Omron CX-Programmer project NuevoProyecto (CX-Programmer 9.51)

# PLC NuevoPLC1: CJ1M CPU12
I/O table (CPU CJ1M-CPU12): rack 0 slot 0 CJ1W-DRM21; rack 0 slot 1 CJ1W-ID211; rack 0 slot 2 CJ1W-ID211; rack 0 slot 3 CJ1W-ID211; rack 0 slot 4 CJ1W-OD212; rack 0 slot 5 CJ1W-OC211; rack 0 slot 6 CJ1W-OC211; rack 0 slot 7 CJ1W-ID211

## Global symbols (name address type ; comment)
Acceleracio _INVDRT401_WriteParameter
Acceleracio_SP D1200 UINT  ; Consigna d'acceleració
ActivarExpulsor 11.11 BOOL  ; 13Y1 Expulsor Activat
Alarma 60.00 BOOL  ; Alarma genèrica
Alarma00 61.00 BOOL  ; Protecció tèrmica equip rebobinador
Alarma01 61.01 BOOL  ; Protecció tèrmica equip arrosegament
Alarma02 61.02 BOOL  ; Protecció tèrmica equip carro
Alarma03 61.03 BOOL  ; Protecció tèrmica equip alineador
Alarma04 61.04 BOOL  ; Motor alineador no preparat
Alarma05 61.05 BOOL  ; Tèrmic extractor de retall
Alarma06 61.06 BOOL  ; Detectors de retall
Alarma07 61.07 BOOL  ; Alarma pressió aire
Alarma08 61.08 BOOL
Alarma09 61.09 BOOL
Alarma10 61.10 BOOL
Alarma11 61.11 BOOL
Alarma12 61.12 BOOL
Alarma13 61.13 BOOL
Alarma14 61.14 BOOL
Alarma15 61.15 BOOL
Alarma16 62.00 BOOL
Alarma17 62.01 BOOL
Alarma18 62.02 BOOL
Alarma19 62.03 BOOL
Alarma20 62.04 BOOL
Alarma21 62.05 BOOL
Alarma22 62.06 BOOL
Alarma23 62.07 BOOL
Alarma24 62.08 BOOL
Alarma25 62.09 BOOL
Alarma26 62.10 BOOL
Alarma27 62.11 BOOL
Alarma28 62.12 BOOL
Alarma29 62.13 BOOL
Alarma30 62.14 BOOL
Alarma31 62.15 BOOL
AlarmaActiva 60.02 BOOL  ; Alarma activa
AlarmaCritica 60.01 BOOL  ; Alarma critica, aturada inmediata de màquina
AlarmaCritica00 63.00 BOOL  ; Paro d'emergència activat
AlarmaCritica01 63.01 BOOL  ; Motor rebobinador no preparat
AlarmaCritica02 63.02 BOOL  ; Motor arrastre no preparat
AlarmaCritica03 63.03 BOOL  ; Motor carro no preparat
AlarmaCritica04 63.04 BOOL  ; Braç suport rebobinador fora de posició
AlarmaCritica05 63.05 BOOL  ; Porta desbobinador oberta
AlarmaCritica06 63.06 BOOL  ; Seguretat diametre màxim de bobina
AlarmaCritica07 63.07 BOOL  ; Seguretat pisor 1 endarrera
AlarmaCritica08 63.08 BOOL  ; Seguretat pisor 2 endarrera
AlarmaCritica09 63.09 BOOL
AlarmaCritica10 63.10 BOOL
AlarmaCritica11 63.11 BOOL
AlarmaCritica12 63.12 BOOL
AlarmaCritica13 63.13 BOOL
AlarmaCritica14 63.14 BOOL
AlarmaCritica15 63.15 BOOL
AlarmaCritica16 64.00 BOOL
AlarmaCritica17 64.01 BOOL
AlarmaCritica18 64.02 BOOL
AlarmaCritica19 64.03 BOOL
AlarmaCritica20 64.04 BOOL
AlarmaCritica21 64.05 BOOL
AlarmaCritica22 64.06 BOOL
AlarmaCritica23 64.07 BOOL
AlarmaCritica24 64.08 BOOL
AlarmaCritica25 64.09 BOOL
AlarmaCritica26 64.10 BOOL
AlarmaCritica27 64.11 BOOL
AlarmaCritica28 64.12 BOOL
AlarmaCritica29 64.13 BOOL
AlarmaCritica30 64.14 BOOL
AlarmaCritica31 64.15 BOOL
AlineadorReady 3340.05 BOOL  ; Equip Alineador ready
AnalogOutFreDesbo _INVDRT401_WriteParameter
ArrancExtractorRetall 12.02 BOOL  ; 17K2 Arranc extractor de retall
ArrosegamentReady 3320.05 BOOL  ; Equip Arrosegament ready
110.00 BOOL  ; Friccio eix 1 busy
110.01 BOOL  ; Senyal friccio eix 2 busy
111.00 BOOL  ; Off/On freno rebobinador
200.00 BOOL  ; AuxAccelBusy
200.01 BOOL  ; AuxDesaccelBusy
200.02 BOOL  ; Peticio actualitzacio acceleracio
200.03 BOOL  ; Actualitzacio acceleracio finalitzada
200.04 BOOL  ; Peticio actualitzacio desacceleracio
200.05 BOOL  ; Actualitzacio desacceleracio finalitzada
2960.08 BOOL  ; Entrada comptatge lector de marques
301.00 BOOL  ; Senyal consigna fre busy
301.01 BOOL  ; Senyal diametre desbo busy
302.00 BOOL  ; Auxiliar senyal desbobinador
304.00 BOOL  ; Aux Run Fw alineador manual
304.01 BOOL  ; Aux Run Rv alineador manual
3210.00 BOOL  ; Run Fw motor rebobinador
3210.01 BOOL  ; Run Rv motor rebobinador
3211 CHANNEL  ; Velocitat en Hz motor rebo
3221 CHANNEL  ; Referencia frequencia equip arrosegament en Hz
3231 CHANNEL  ; Referencia velocitat equip carro
3241 CHANNEL  ; Referencia velocitat alineador
3311.00 BOOL  ; Protecció termic RW
3321 CHANNEL  ; Feedback frequencia equip arrosegament
3360 CHANNEL  ; Diametre rebobinador
400.00 BOOL  ; Senyal Pressio pisor 1 busy
400.04 BOOL  ; Finalitzada actualitzacio de presio de pisor 1
400.05 BOOL  ; Peticio actualitzacio pressio pisor 1
400.06 BOOL  ; Finalitzacio actualitzacio pressio pisor 2
400.07 BOOL  ; Peticio actualitzacio pressio pisor 2
401 CHANNEL  ; Sequencia carro
402.00 BOOL  ; Reset encoder carro
402.01 BOOL  ; busy preset carro
403.02 BOOL  ; Auxiliar carro fw
403.03 BOOL  ; Auxiliar carro Rv
403.04 BOOL  ; AuxMotorCarro
403.05 BOOL  ; AuxMotorBrasos
403.06 BOOL  ; Retard Conexio Contactor
403.07 BOOL  ; Tope carro darrera
410 CHANNEL  ; Sequencia pujar/baixar braços
410.00 BOOL  ; Pujar motor braços suport
410.01 BOOL  ; Baixar motor braços suport eixos
420.00 BOOL  ; Generar preset de posició encoder
500.00 BOOL  ; Mode alineador
500.01 BOOL  ; AuxAlineadorFw
500.02 BOOL  ; AuxAlineadorRv
500.03 BOOL  ; Actualitzacio guany P alineador feta
500.04 BOOL  ; Flanc inici alineador mode automàtic
500.05 BOOL  ; Ok inici run alineador mode automàtic
500.06 BOOL  ; Ctrl mode velocitat alineador
501.02 BOOL  ; Peticio actualitzacio guany P alineador
51 CHANNEL  ; Estat Màquina
52.03 BOOL  ; Màquina en moviment
52.04 BOOL  ; Condicions braços suport Ok
54.00 BOOL  ; Senyal inici paro per metres
54.01 BOOL  ; Paro per diametre desbobinador
54.02 BOOL  ; Senyal paro automatic per diametre desbo
54.03 BOOL  ; ParoPerDiametreDesbo
54.04 BOOL  ; DiametreReboSuperat
54.15 BOOL  ; Senyal paro automàtic comptadors
600.01 BOOL  ; Aux pinces carro rebo menys
D10000 CHANNEL  ; ç
D1100 CHANNEL  ; Fricció eix 1
D1101 CHANNEL  ; Fricció eix 2
D1112 CHANNEL  ; Decreixent tiro rebobinador
D1113 CHANNEL  ; Ample bobina rebo 1
D1114 CHANNEL  ; Pressio friccio rebo 1
D1122 CHANNEL  ; Decreixent tieo rebo 2
D1123 CHANNEL  ; Ample bobina rebo 2
D1130 CHANNEL  ; Offset corba parell eix friccio
D1131 CHANNEL  ; Sortida pressio mínima
D1205 CHANNEL  ; Selecció actual desacceleració
D1400 CHANNEL  ; Pressio pisor eix 1
D1401 CHANNEL  ; Auxiliar presió pisor 1
D1402 CHANNEL  ; Posició pisor eix 1
D1403 CHANNEL  ; Posició pisor eix 2
D1405 CHANNEL  ; Error posició pisor 1
D1410 CHANNEL  ; Pressio pisor 2
D1412 CHANNEL  ; Posicio pisor rebo 2
D1415 CHANNEL  ; Error posicio pisor 2
D1420 CHANNEL  ; Tope carro endarrera
D1490 CHANNEL  ; Tope carro enrera
D1500 CHANNEL  ; Tensió capçar alineador
D1501 CHANNEL  ; ErrorAlineador
D1502 CHANNEL  ; Velocitat maxima alineador Fw
D1503 CHANNEL  ; Velocitat alineador maxima Rv
D1505 CHANNEL  ; Velocitat inici alineador
D1510 CHANNEL  ; Guany P alineador
D1520 CHANNEL  ; Aux Guany P alineador
D1601 CHANNEL  ; Velocitat minima deteccio retall
D1602 CHANNEL  ; Mode avis/paro detectors retall
D216 CHANNEL  ; MetresParoDesbo
H100.00 BOOL  ; Forçar pisor arrosegament
H110.00 BOOL  ; Sentit bobinat
H120.00 BOOL  ; Sentit Alineador
H150.00 BOOL  ; OffOnDetectorRetall1
H150.01 BOOL  ; OffOnDetectorRetall2
H54.00 BOOL  ; Off/On paro per metres
H54.01 BOOL  ; Off/On paro per diametre rebo
H54.02 BOOL  ; Off/On paro per diametre desbobinador
T0051 BOOL  ; Retard apagar ventiladors motors
T0052 BOOL  ; Temps avis alarma
T0053 BOOL  ; Tim avis acustic nou avis
T0054 BOOL  ; Tim avis pistons pneumatics braços
T0100 BOOL  ; Tim presostat aire
T0300 BOOL  ; Retard obertura desbo
T0301 BOOL  ; Retard a la desconexió de la central hidraulica
T0302 BOOL  ; Retard a la desconexió del pisto posició vertical handling
T0303 BOOL  ; Retard a la desconexió del pisto carrega bobines handling
T0400 BOOL  ; Temporitzador retard a la conexió dels contactors de selecció de motor
T0500 BOOL  ; Retard a la conexió del Run alineador respecte el PID
AuxAcceleracio_SP D1201 UINT  ; Auxiliar consigna acceleració
AuxCalcul0 W0 CHANNEL  ; Auxiliar Calcul
AuxCalcul1 W1 CHANNEL  ; Auxiliar Calcul
AuxCalcul2 W2 CHANNEL  ; Auxiliar Calcul
AuxCalcul3 W3 CHANNEL  ; Auxiliar Calcul
AuxCalcul4 W4 CHANNEL  ; Auxiliar Calcul
AuxCalcul5 W5 CHANNEL  ; Auxiliar Calcul
AuxCalcul6 W6 CHANNEL  ; Auxiliar Calcul
AuxDCalcul0 W10 DINT
AuxDCalcul1 W12 DINT
AuxDesacceleracio_SP D1203 UINT  ; Auxiliar consigna desacceleracio
AuxDiametreDresbo_PV D1301 INT  ; Diametre actual desbobinador format %
AuxHusilloDreta 300.00 BOOL  ; Maniobra obrir tencar i desfasar desbo EASY
AuxHusilloEsquerra 300.01 BOOL  ; Maniobra obrir tencar i desfasar desbo EASY
Aux_Paro_Handling 700.00 BOOL  ; Auxiliar Paro Handling
Avis00 81.00 BOOL  ; Pinces carro activades
Avis01 81.01 BOOL  ; Equip rebobinador no preparat
Avis02 81.02 BOOL  ; Equip arrosegament no preparat
Avis03 81.03 BOOL  ; Equip carro no preparat
Avis04 81.04 BOOL  ; Equip alineador no preparat
Avis05 81.05 BOOL  ; Cierres rebobinador posats en intentar moure braços
Avis06 81.06 BOOL  ; Cierres rebobinador trets en intentar donar marxa
Avis07 81.07 BOOL  ; Desbobinador fora de posicio al intentar donar marxa a maquina
Avis08 81.08 BOOL  ; Braços de suport rebobinador fora de posicio
Avis09 81.09 BOOL  ; Pisor arrosegament no baixat en el moment de marxa
Avis10 81.10 BOOL  ; Detectors retall
Avis11 81.11 BOOL  ; Proteccio ganivetas circulars oberta
Avis12 81.12 BOOL  ; Porta seguretat desbobinador oberta
Avis13 81.13 BOOL  ; Expulsors bobines a carrega
Avis14 81.14 BOOL  ; Emegencia Handling
AvisosActius 80.00 BOOL  ; Avisos actius
BI_Centrat 1.12 BOOL  ; 54BI4 Detector posició central alineador desbo EASY
BI_PosicioBraçHoritzontal 3.08 BOOL  ; 22BI1 Detector Handling Posicio Horitzontal
BI_PosicioBraçVertical 3.09 BOOL  ; 22BI2 Detector Handling Posicio Vertical
BI_PosicioPerxaCarrega 3.10 BOOL  ; 22BI3 Detector Handling Posicio Carrega
BI_PosicioPerxaDesrarrega 3.11 BOOL  ; 22BI4 Detector Handling Posicio Descarrega
BI_SeguretatBraçosAmun 2.08 BOOL  ; 14BI3 Posicio braços suport amunt
BI_SeguretatHusillo 1.14 BOOL  ; 54BI6 Detector desbo EASY seguretat husillo
BI_TopeCostatCilindre 1.15 BOOL  ; 54BI7 Detector tope costat cilindre desbo EASY
BI_TopeCostatHusillo 1.10 BOOL  ; 54BI2 Detector desbo EASY tope costat husillo
BI_TopeDesfasaeDreta 1.13 BOOL  ; 54BI5 Detector tope desfasar dreta desbobinador EASY
BI_TopeDesfasarEsquerra 1.11 BOOL  ; 54BI3 Detector desbo EASY tope desfasar esquerra
BaixarDesbobinador 12.07 BOOL  ; 58Y2 Baixar desbobinador
BarresAntiestatica 11.10 BOOL  ; 16K1 Barres antiestàtiques
BarresAntiestatica_Muntat H0.06 BOOL  ; Barres antiestàtiques muntades a màquina
BraçHandlingHoritzontal 12.10 BOOL  ; 62Y2 Braç Handling Posicio Hotirzontal
BraçHandlingVertical 12.09 BOOL  ; 62Y1 Braç Handling Posicio Vertical
CarroManualFw 401.01 BOOL  ; Moviment carro endevant manual
CarroManualRv 401.03 BOOL  ; Moviment carro endarrera manual
CarroManualStopFw 401.02 BOOL  ; Para moviment endevant carro en manual
CarroManualStopRv 401.00 BOOL  ; Para moviment endarrera carro en manual
CarroReady 3330.05 BOOL  ; Equip Carro ready
CentralHidraulica 12.05 BOOL  ; 57K1 Central hidràulica
Claxon 10.09 BOOL  ; Claxon
CntMetresParcial D202 INT  ; Registre comptatge metres
CntMetresTotal D206 DINT  ; Totalitzador metres
CntPulsosParcial D200 INT  ; Comptador de metres actual
CntPulsosTotal D204 DINT  ; Comptador pulsos lleva totals
ComptaMetres 0.14 BOOL  ; 24BI1 Inductiu lleva comptamentres
ComptadorMarques D220 DINT  ; Lectura comptador de marques
CondicionsMarxaOK 52.00 BOOL  ; Condicions per a l'inici de la marxa de màquina
CtrlFreArrosegament 100.01 BOOL  ; Off/On Fre arrosegament
CtrlPisorArrosegament 100.00 BOOL  ; Off/On pisor arrosegament
CtrlVelocitatSeguretat D106 INT  ; Velocitat de seguretat de control
DB_CapsalAlineador _INVDRT201_ReadParameter
DB_DiametreDesbo Escalat
DB_DiametreDesbo_PV _INVDRT201_ReadParameter
DB_ErrorAlineador Escalat
DB_ErrorPosicioPisor1 Escalat
DB_ErrorPosicioPisor2 Escalat
DB_Fre Escalat
DB_VelocitatActual Escalat
DB_VelocitatLineaHz Escalat
DemHidraHandling 700.02 BOOL  ; Demanda central hidraulica handlind
Desacceleracio _INVDRT401_WriteParameter
Desacceleracio_SP D1202 UINT  ; Consigna desacceleracio
DesactivarExpulsor 11.12 BOOL  ; 13Y2 Desactivar Expulsor
DetectorRetall1 2.11 BOOL  ; 17BF1 Detector extractor de retall 1
DetectorRetall2 2.12 BOOL  ; 17BF2 Detector extractor de retall 2
DetectorsRetall_Muntat H0.03 BOOL  ; Detectors extractor de retall muntats a la màquina
DiametreDesbo_PV D1302 INT  ; Diametre desbobinador en mm
DiametreMaximDesbo D1304 INT  ; Diametre màxim desbobinador en mm
DiametreMaximRebo D1105 INT  ; Diametre màxim rebobinador
DiametreMinimDesbo D1305 INT  ; Diametre core desbobinador
DiametreMinimRebo D1104 INT  ; Diametre mínim de rebobinador
DiametreStopDesbo D212 INT  ; Diametre paro automàtic desbobinador
DiametreStopRebo D213 INT  ; Diametre paro automatic rebobinador
DistanciaMarques D222 DINT  ; Distancia entre marques en mm
EmergenciaHandling 3.12 BOOL  ; Handling en estat d'emergencia
Emergència 0.00 BOOL  ; Relé de seguretat
EnclavamentPortaDesbo 10.11 BOOL  ; 16K1 Enclavament seguretat porta desbobinador
EquipsReady 52.02 BOOL  ; Equips ready
Escaner_Seguretat 3.13 BOOL  ; Escaner Seguretat
Estat 50 WORD  ; Bits d'estat de màquina
EstatDetectorsRetall 151.00 BOOL  ; Detectors retall Ok
EstatMaquinaParadaOk 52.01 BOOL  ; Condicions de màquina aturada
Estat_Alarma 50.01 BOOL  ; Màquina en estat d'alarma
Estat_Enfilat 50.06 BOOL  ; Màquina amb marxa d'enfilat
Estat_Marxa 50.04 BOOL  ; Màquina en producció
Estat_Paro 50.05 BOOL  ; Màquina en procés de paro convencional
Estat_Preparacio 50.03 BOOL  ; Maquina en estat de preparació
Estat_Stop 50.02 BOOL  ; Màquina aturada sense alarmes
Estat_emergència 50.00 BOOL  ; Màquina en estat de paro d'emergència
ExpulsorFora 3.02 BOOL  ; 13B1 Reed Expulsor Fora
ExpulsorHome 3.03 BOOL  ; 13B2 Reed Expulsor Home
Expulsors_Muntats H0.10 BOOL  ; Expulsors instal.lats a màquina
ExtractorRetall 12.01 BOOL  ; 17K1 Extractor retall
ExtractorRetall_Muntat H0.01 BOOL  ; Extractor de retall muntat a la màquina
FlagVelocitatSeguretat 52.05 BOOL  ; Senyal màquina en velocitat de seguretat
ForçarExtractorRetall H101.00 BOOL  ; Forçar extractor de retall
Fre Escalat
FreArrosegament 11.05 BOOL  ; 33Y2 Fre arrosegament
FreRebobinador 11.00 BOOL  ; 14Y1 Fre rebobinador
FriccioEix1 FriccioEix1
FriccioRebo1 FriccioEix2
FriccioRebo2 FriccioEix2
Friccio_1_Prova _INVDRT401_WriteParameter
FriccióEix1 _INVDRT401_WriteParameter
FriccióEix2 _INVDRT401_WriteParameter
GruixMaterial D211 INT  ; Espesor
GuanyOutPID_Alineador _INVDRT401_WriteParameter
Handling_Muntat H0.09 BOOL  ; Hanfling instal.lat a màquina
LaserMandrins 11.09 BOOL  ; 15K1 Laser posicionador mandrins
LaserMandrins_Muntat H0.04 BOOL  ; Laser posicionat mandrins muntats a la màquina
LectorMarques H0.08 BOOL  ; Lector de marques muntat
ManAutHandling 700.01 BOOL  ; Handling en manual automàtic
Metres2Marques D228 INT  ; Conversió el preset de marques a metres
MetresAproximacio D210 INT  ; Metres aproximació
MetresMarques D224 INT  ; Conversió de marques a mm
MetresParoAutomatic D208 INT  ; Metres de bobina per paro automatic
ModeAcceleracio 53.00 BOOL  ; Mode Acceleracio auto/man
ModeVelocitat 53.01 BOOL  ; Velocitat On=Ràpida Off=Lenta
MotorBraçosSuport 12.04 BOOL  ; 24K2 Contactor selecció motor braços suport
MotorCarro 12.03 BOOL  ; 24K1 Contactor selecció motor carro
ObrirDesboEASY 11.08 BOOL  ; 54Y2 Obrir desbobinador EASY
OffOnBarresAntiestàtiques H110.01 BOOL  ; Off/On barres antiestàtiques
OffOnDesbo 300.02 BOOL  ; Biestable Off/On desbobinador
OffOnExtractorRetall 150.00 BOOL  ; Off/On extractor de retall
OffOnLaserMandrins 150.01 BOOL  ; Off/On Laser posicionat mandrins
OffOnMarques H54.03 BOOL  ; Off/On paro per marques
OffOnPID_Alineador _INVDRT401_WriteParameter
OffsetEscalatDiametreDesbo D1303 INT  ; Offset escalat diametre desbo
OffsetFre D1313 INT  ; Offset sortida fre
OnOffTanquesBraços 11.13 BOOL  ; 14K2 Obrir/tancar pistons pneumatics braços
OscilacioGanivetas 12.08 BOOL  ; 18K1 Contactor motor oscil.lacio ganivetas
OscilacioGanivetas_Muntat H0.02 BOOL  ; Oscilacio Ganivetas muntat a la màquina
PID_Alineador 3240.05 BOOL  ; Off/On PID Alineador
ParellFre_SP D1311 INT  ; Consigna fre a aplicar en %
ParellMaxFre D1312 INT  ; Parell màxim que pot exercir el fre en kg*m
ParoAutomatic 70.00 BOOL  ; Paro automatic de màquina
ParoDetRetall 151.01 BOOL  ; Paro per detectors retall
ParoMarques 54.05 BOOL  ; Paro per marques
ParoRapid D1204 INT  ; Temps desacceleració per paro ràpid
ParoRapidDetRetall 151.02 BOOL  ; Paro rapid per detectors retall
PerimetreArrosegament D201 INT  ; Perimetre rodillo arrosegament
PerxaCarrega 12.12 BOOL  ; 62Y4 Perxa Posicio Carrega
PerxaDescarrega 12.11 BOOL  ; 62Y3 Perxa Posicio Descarrega
PickUp_Muntat H0.00 BOOL  ; PickUp instal.lat a la màquina
PilotAlineador 10.07 BOOL  ; 44SH1 Pilot pulsador alineador
PilotContadorMarques 10.12 BOOL  ; 35SH1 Pilot pulsador contador marques
PilotDesbobinador 10.08 BOOL  ; 53SH1 Pilot pulsador desbobinador
PilotExtractor 10.04 BOOL  ; 17SH1 Pilot pulsador extractor de retall
PilotFreArrosegament 10.06 BOOL  ; 33SH2 Pilot pulsador fre arrosegament
PilotMarxa 10.02 BOOL  ; 08SH3 Pilot pulsador de marxa
PilotModeAcceleracio 10.03 BOOL  ; 08SH7 Pilot pulsador mode acceleració
PilotParo 10.01 BOOL  ; 08SH1 Pilot pulsador de paro
PilotPisorArrosegament 10.05 BOOL  ; 33SH1 Pilot pulsador pisor arrosegament
PilotReset 10.00 BOOL  ; 06SH1 Pilot pulsador de reset
PilotSelectorPorta 10.10 BOOL  ; 08SH15 Pilot selector obrir porta seguretat desbo
PincesCarroMenys 11.02 BOOL  ; 23Y1 Pinces carro a menys
PincesCarroMes 11.03 BOOL  ; 23Y2 Pinces carro a més
PisorArrosegament 11.04 BOOL  ; 33Y1 Pisor arrosegament
PisorRetenidor 11.06 BOOL  ; 34Y1 Pisor retenidor
PosicioPisor1 _INVDRT201_ReadParameter
PosicioPisor2 _INVDRT201_ReadParameter
PresetEncoderCarro _INVDRT401_WriteParameter
PresioMaximaFriccio D1107 INT  ; Pressió màxima
PresorRebobinador 11.01 BOOL  ; 14Y2 Presor rebobinador
PresostatGeneral 0.15 BOOL  ; 34B1 Presostat linea general
PressioPisor1 _INVDRT401_WriteParameter
PressioPisor2 _INVDRT401_WriteParameter
ProteccioTermicaAlineador 3344.00 BOOL  ; Protecció tèrmica Alineador entrada S1
ProteccioTermicaArrosegament 3324.00 BOOL  ; Protecció tèrmica Arrosegament entrada S1
ProteccioTermicaCarro 3334.00 BOOL  ; Protecció tèrmica Carro entrada S1
ProteccioTermicaRebo 3314.00 BOOL  ; Protecció tèrmica Rebo entrada S1
PujarDesbobinador 12.06 BOOL  ; Pujar Desbobinador
RebobinadorReady 3310.05 BOOL  ; Equip Rebobinador ready
RegistreAlarma 60 DWORD  ; Registre alarmes
RegistreAlarmaCritica 63 DWORD  ; Registre alarma crítica
RegistreAvisos 81 CHANNEL  ; Registre avisos
ResetAlineador 3240.09 BOOL  ; Reset equip alineador
ResetCarro 3230.09 BOOL  ; Reset equip carro
ResetMarques 55.00 BOOL  ; Reset comptador de marques
RunFwAlineador 3240.00 BOOL  ; Run Fw motor alineador
RunFwArrosegament 3220.00 BOOL  ; Senyal Run forward equip arrosegament
RunFwCarro 3230.00 BOOL  ; Run Carro Fw
RunRvAlineador 3240.01 BOOL  ; Run Rv motor alineador
RunRvArrosegament 3220.01 BOOL  ; Senyal Run reverse equip arrosegament
RunRvCarro 3230.01 BOOL  ; Run Carro Rv
SF_PortaSeguretatDesbo 2.14 BOOL  ; 08SF1 Detector porta seguretat On=Porta tencada Off=Porta oberta
SL_Ajustos 3.14 BOOL  ; 07SL2 Selector Ajustos
SL_BraçAbaix 0.11 BOOL  ; Selector braços suport eixos rebobinador abaix
SL_BraçAmun 0.10 BOOL  ; Selector braços suport eixos rebobinador amunt
SL_OscilacioGanivetas 2.10 BOOL  ; 18SL1 Selector oscil.lacio ganivetas
SL_PortaSeguretat 2.13 BOOL  ; 08SL15 Selector obrir porta seguretat
SP_ActivarExpulsor 3.00 BOOL  ; 13S1Pulsador Activar Expulsor
SP_Alineador 1.00 BOOL  ; 44SH1 Pulsador mode alineador
SP_Augmentar 0.07 BOOL  ; 08SP11 Pulsador augmentar velocitat
SP_BaixarDesbo 2.03 BOOL  ; 57SP1 Pulsador baixar desbobinador
SP_Carro 0.09 BOOL  ; 23SP1 Pulsador carro
SP_DesactivarExpulsor 3.01 BOOL  ; 13S1Pulsador Desactivar Expulsor
SP_Desbobinador 1.03 BOOL  ; SP Pulsador Off/On desbobinador
SP_DesfasarDreta 1.02 BOOL  ; 44SP5 Pulsador desfasar dreta
SP_DesfasarEsquerra 1.01 BOOL  ; 44SP3 Pulsador desfasar esquerra
SP_Disminuir 0.06 BOOL  ; 08SP9 Pulsador disminuir velocitat
SP_Enfilat 0.08 BOOL  ; 08SP13 Pulsador enfilat
SP_ExtractorRetall 2.00 BOOL  ; 17SH1 Pulsador Off/On extractor de retall
SP_FreArrosegament 0.13 BOOL  ; 33SH2 Pulsador Off/On fre arrosegament
SP_HandlingStop 3.07 BOOL  ; 61SP2 Pulsador Handling Stop
SP_Marxa 0.03 BOOL  ; 08SH3 Pulsador de marxa
SP_ModeAccel 0.05 BOOL  ; 08SH7 Pulsador mode acceleracio Manual/Automatica
SP_MovimentHandling 3.04 BOOL  ; 61SP1 Pulsador Moviment Handling
SP_ObrirDesbo 2.06 BOOL  ; 55SP1 Pulsador obrir desbobinador
SP_Paro 0.02 BOOL  ; 08SH1 Pulsador paro
SP_ParoRapid 0.04 BOOL  ; 08SP5 Pulsador paro ràpid
SP_PisorArrosegament 0.12 BOOL  ; 33SH1 Pulsador Off/On pisor arrosegament
SP_PujarDesbo 2.04 BOOL  ; 57SP2 Pulsador pujar desbobinador
SP_Reset 0.01 BOOL  ; 06SH1 Pulsador reset
SP_RotacioHandlingHoritzontal 3.05 BOOL  ; 61S1 Pulsador Rotacio Horitzontal Handling
SP_RotacioHandlingVertical 3.06 BOOL  ; 61S1Pulsador Rotacio Vertical Handling
SP_SeguretatDesbo 2.09 BOOL  ; 57SP3 Pulsador seguretat maniobra hidràulica
SP_TencarDesbo 2.07 BOOL  ; 55SP2 Pulsador tencar desbobinador
SafetyPLC H0.12 BOOL  ; Safety PLC installed
SclDiaDesboMax D2002 INT  ; Valor màxim entrada analogica diametre desbo escalat
SclDiaMaxDesbo D2001 INT  ; Diametre màxim desbo escalat
SclOffsetDiaDesbo D2000 INT  ; Offset escalat diametre desbo
SeguretatBraçAbaix 1.07 BOOL  ; 14SF2 Final de cursa seguretat posició braços suport rebobinador abaix
SeguretatBraçAmun 1.06 BOOL  ; 14SF1 Final de cursa seguretat posició braços suport rebobinador amun
SeguretatCirculars 2.15 BOOL  ; 08BI1 Detector seguretat protecció ganivetas circulars
SeguretatPincesCarro 1.08 BOOL  ; 23BI1 Reed seguretat pinces carro pisor a menys
SeguretatPisorOff 700.03 BOOL  ; Seguretat pisor totalment endavant
SeguretatPosicioDesbo 2.05 BOOL  ; 58SF1 Final de cursa seguretat posició Desbobinador
SeguretatTancamentRebo1 1.04 BOOL  ; 14BI1 Inductiu seguretat tancament rebobinador 1
SeguretatTancamentRebo2 1.05 BOOL  ; 14BI2 Inductiu seguretat tancament eix rebobinador 2
SeguretatTencarDesbo 1.09 BOOL  ; 54BI1 Reed seguretat cilindre tancament desbobinador
SobrevelocitatRebo D1103 INT  ; Sobrevelocitat rebobinador en m/min
SortidaFre D1314 WORD
TallCirculars_Muntat H0.07 BOOL  ; Tall de ganivetas circulars muntat
Tanques_Rebo_Muntats H0.11 BOOL  ; Tanques pneumatiques a màquina
TaperRebo1 D1111 INT  ; Taper tir rebobinador 1
TaperRebo2 D1121 INT  ; Taper tir rebobinador 2
TempsLaserMandrinsOn D1600 CHANNEL  ; Temps On Laser posicionat mandrins
TencarDesboEASY 11.07 BOOL  ; 54Y1 Tencar desbobinador EASY
TencatDesbo_Muntat H0.05 BOOL  ; Tencat desbobinador de seguretat muntat a màquina
TensioDesbo_SP D1310 INT  ; Consigna de fre al desbobinador
TimArrancExtractorRetall T0150 BOOL  ; Temporització per a l'arranc del extractor de retall
TimLaserMandrins T0151 BOOL  ; Temporització On laser mandrins
TimPisor1 T0101 BOOL  ; Temporització seguretat pisor1
TimPisor2 T0102 BOOL  ; Temporització seguretat pisor2
TimPreparacio T0050 BOOL  ; Temporització del estat de preparacio de marxa
TirMaximRebo D1106 INT  ; Tir màxim rebobinador
TirRebo1_SP D1110 INT  ; Consigna de tir rebobinador 1
TirRebo2_SP D1120 INT  ; Consigna de tir rebobinador 2
TiroDesboMax D1315 INT  ; Tiro màxim aplicable al desbo
TiroRebo1 Escalat
TiroRebo2 Escalat
TèrmicCentralHidràulica 2.02 BOOL  ; 57F1 Tèrmic central hidràulica
TèrmicExtractorRetall 2.01 BOOL  ; 17F1 Tèrmic extractor de retall
Velocitat0Arrosegament 3320.01 BOOL  ; Velocitat 0 equip arrosegament
Velocitat0Carro 3330.01 BOOL  ; Velocitat 0 equip carro
Velocitat0Rebo 3310.01 BOOL  ; Velocitat 0 equip rebo
VelocitatActual D110 INT  ; Velocitat actual de màquina m/min
VelocitatAuto D101 INT  ; Velocitat automàtica
VelocitatEnfilat D104 INT  ; Velocitat enfilat
VelocitatExpulsioBobines D107 INT  ; Velocitat del Rebobinador al expulsar bobina
VelocitatLenta D102 INT  ; Velocitat lenta
VelocitatLineaRebo D1102 CHANNEL  ; Velocitat en Hz de motor rebo
VelocitatMaxima D103 INT  ; Velocitat màxima
VelocitatSeguretat D105 INT  ; Velocitat de seguretat
VelocitatSeguretatPLC 10.13 BOOL  ; Velocitat seguretat PLC
Velocitat_SP D100 INT  ; Consigna velocitat
Velocitat_braços D112 INT  ; Velocitat braços
Velocitat_carro D1406 INT  ; Velocitat del carro
VentiladorsMotors 12.00 BOOL  ; 08K1 Contactor ventilació motors

## Program Màquina (cyclic task 0)
Local symbols
Aux_Paro_handling BOOL
Aux_StopHandling BOOL
BI_TopeDesfasarDreta BOOL
Estat_Emerencia BOOL
Estat_Emergencia BOOL
Estat_Emergència BOOL
Estat_emergencia BOOL
IR CHANNEL
P_G BOOL
P_GR BOOL
P_Ge BOOL
P_ON BOOL
P_on BOOL
S UINT
SP_Stop BOOL
sp_reset BOOL

### Section EstatMàquina

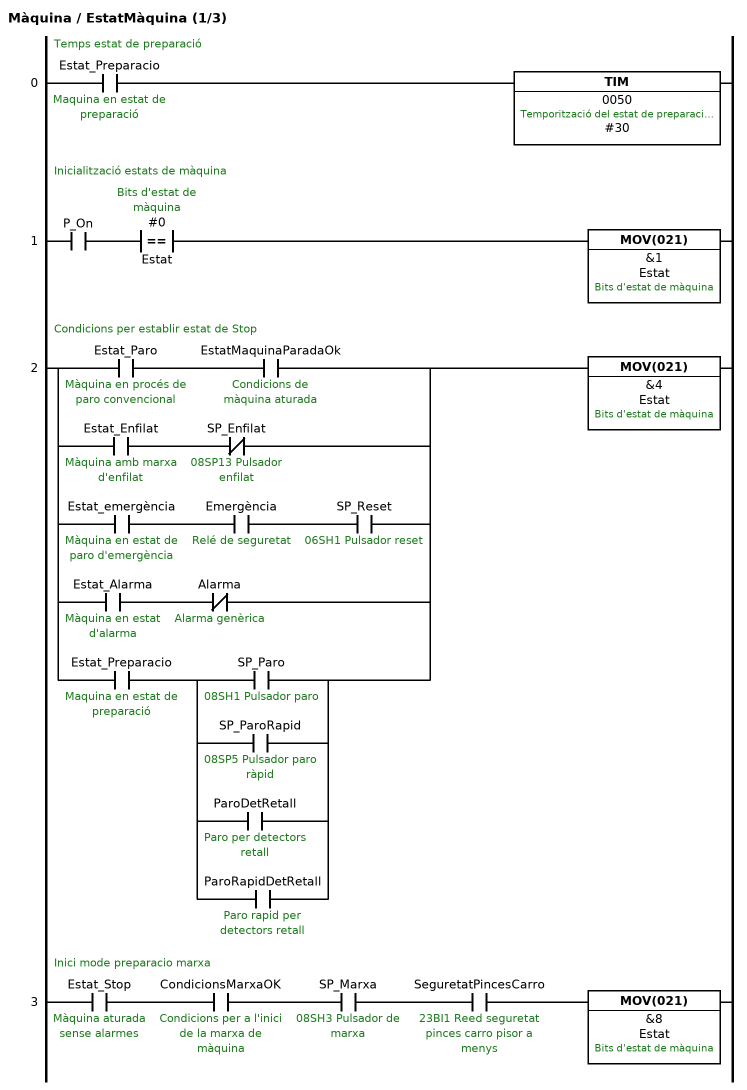
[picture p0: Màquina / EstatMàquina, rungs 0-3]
; rung 0: Temps estat de preparació
LD Estat_Preparacio  ; Maquina en estat de preparació
TIM 0050 #30  ; Temporització del estat de preparacio de marxa
; rung 1: Inicialització estats de màquina
LD P_On
AND=(300) #0 Estat  ; Bits d'estat de màquina
MOV(021) &1 Estat  ; Bits d'estat de màquina
; rung 2: Condicions per establir estat de Stop
LD Estat_Paro  ; Màquina en procés de paro convencional
AND EstatMaquinaParadaOk  ; Condicions de màquina aturada
LD Estat_Enfilat  ; Màquina amb marxa d'enfilat
ANDNOT SP_Enfilat  ; 08SP13 Pulsador enfilat
ORLD
LD Estat_emergència  ; Màquina en estat de paro d'emergència
AND Emergència  ; Relé de seguretat
AND SP_Reset  ; 06SH1 Pulsador reset
ORLD
LD Estat_Alarma  ; Màquina en estat d'alarma
ANDNOT Alarma  ; Alarma genèrica
ORLD
LD Estat_Preparacio  ; Maquina en estat de preparació
LD SP_Paro  ; 08SH1 Pulsador paro
OR SP_ParoRapid  ; 08SP5 Pulsador paro ràpid
OR ParoDetRetall  ; Paro per detectors retall
OR ParoRapidDetRetall  ; Paro rapid per detectors retall
ANDLD
ORLD
MOV(021) &4 Estat  ; Bits d'estat de màquina
; rung 3: Inici mode preparacio marxa
LD Estat_Stop  ; Màquina aturada sense alarmes
AND CondicionsMarxaOK  ; Condicions per a l'inici de la marxa de màquina
AND SP_Marxa  ; 08SH3 Pulsador de marxa
AND SeguretatPincesCarro  ; 23BI1 Reed seguretat pinces carro pisor a menys
MOV(021) &8 Estat  ; Bits d'estat de màquina

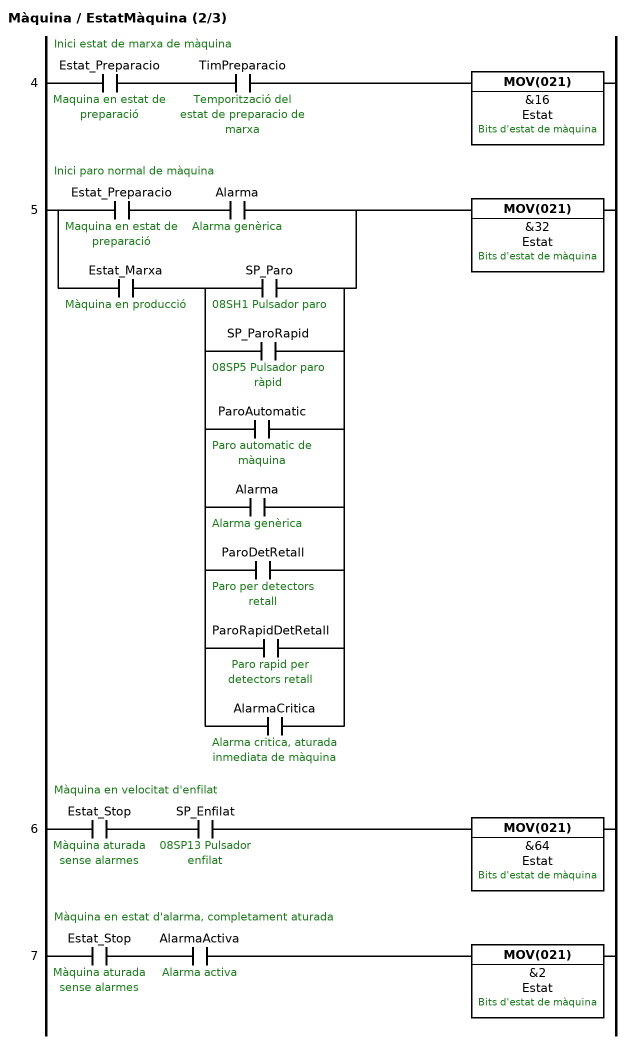
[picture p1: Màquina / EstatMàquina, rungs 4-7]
; rung 4: Inici estat de marxa de màquina
LD Estat_Preparacio  ; Maquina en estat de preparació
AND TimPreparacio  ; Temporització del estat de preparacio de marxa
MOV(021) &16 Estat  ; Bits d'estat de màquina
; rung 5: Inici paro normal de màquina
LD Estat_Preparacio  ; Maquina en estat de preparació
AND Alarma  ; Alarma genèrica
LD Estat_Marxa  ; Màquina en producció
LD SP_Paro  ; 08SH1 Pulsador paro
OR SP_ParoRapid  ; 08SP5 Pulsador paro ràpid
OR ParoAutomatic  ; Paro automatic de màquina
OR Alarma  ; Alarma genèrica
OR ParoDetRetall  ; Paro per detectors retall
OR ParoRapidDetRetall  ; Paro rapid per detectors retall
OR AlarmaCritica  ; Alarma critica, aturada inmediata de màquina
ANDLD
ORLD
MOV(021) &32 Estat  ; Bits d'estat de màquina
; rung 6: Màquina en velocitat d'enfilat
LD Estat_Stop  ; Màquina aturada sense alarmes
AND SP_Enfilat  ; 08SP13 Pulsador enfilat
MOV(021) &64 Estat  ; Bits d'estat de màquina
; rung 7: Màquina en estat d'alarma, completament aturada
LD Estat_Stop  ; Màquina aturada sense alarmes
AND AlarmaActiva  ; Alarma activa
MOV(021) &2 Estat  ; Bits d'estat de màquina

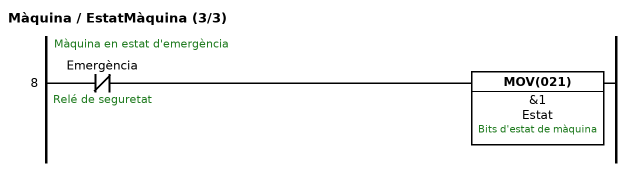
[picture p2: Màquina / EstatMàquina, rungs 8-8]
; rung 8: Màquina en estat d'emergència
LDNOT Emergència  ; Relé de seguretat
MOV(021) &1 Estat  ; Bits d'estat de màquina

### Section Principal

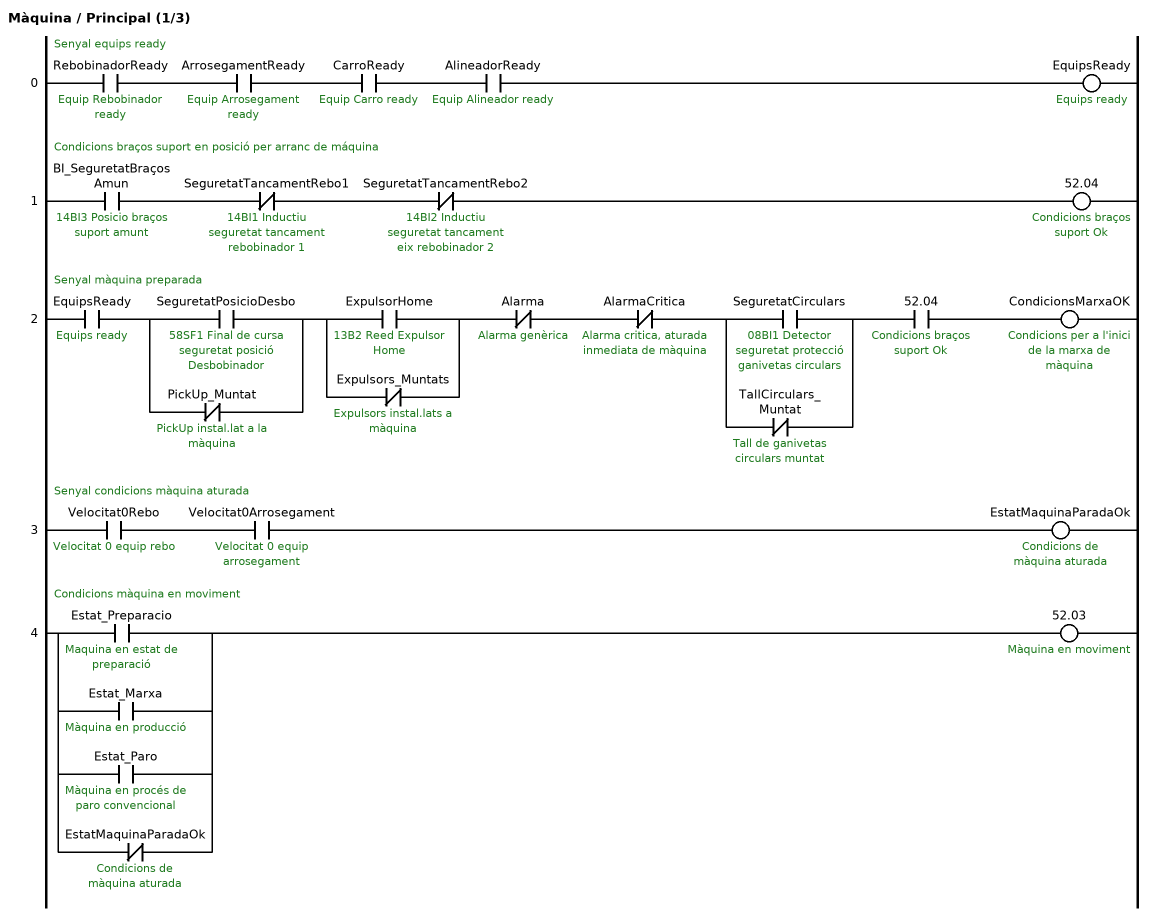
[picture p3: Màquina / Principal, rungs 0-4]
; rung 0: Senyal equips ready
LD RebobinadorReady  ; Equip Rebobinador ready
AND ArrosegamentReady  ; Equip Arrosegament ready
AND CarroReady  ; Equip Carro ready
AND AlineadorReady  ; Equip Alineador ready
OUT EquipsReady  ; Equips ready
; rung 1: Condicions braços suport en posició per arranc de máquina
LD BI_SeguretatBraçosAmun  ; 14BI3 Posicio braços suport amunt
ANDNOT SeguretatTancamentRebo1  ; 14BI1 Inductiu seguretat tancament rebobinador 1
ANDNOT SeguretatTancamentRebo2  ; 14BI2 Inductiu seguretat tancament eix rebobinador 2
OUT 52.04  ; Condicions braços suport Ok
; rung 2: Senyal màquina preparada
LD EquipsReady  ; Equips ready
LD SeguretatPosicioDesbo  ; 58SF1 Final de cursa seguretat posició Desbobinador
ORNOT PickUp_Muntat  ; PickUp instal.lat a la màquina
ANDLD
LD ExpulsorHome  ; 13B2 Reed Expulsor Home
ORNOT Expulsors_Muntats  ; Expulsors instal.lats a màquina
ANDLD
ANDNOT Alarma  ; Alarma genèrica
ANDNOT AlarmaCritica  ; Alarma critica, aturada inmediata de màquina
LD SeguretatCirculars  ; 08BI1 Detector seguretat protecció ganivetas circulars
ORNOT TallCirculars_Muntat  ; Tall de ganivetas circulars muntat
ANDLD
AND 52.04  ; Condicions braços suport Ok
OUT CondicionsMarxaOK  ; Condicions per a l'inici de la marxa de màquina
; rung 3: Senyal condicions màquina aturada
LD Velocitat0Rebo  ; Velocitat 0 equip rebo
AND Velocitat0Arrosegament  ; Velocitat 0 equip arrosegament
OUT EstatMaquinaParadaOk  ; Condicions de màquina aturada
; rung 4: Condicions màquina en moviment
LD Estat_Preparacio  ; Maquina en estat de preparació
OR Estat_Marxa  ; Màquina en producció
OR Estat_Paro  ; Màquina en procés de paro convencional
ORNOT EstatMaquinaParadaOk  ; Condicions de màquina aturada
OUT 52.03  ; Màquina en moviment

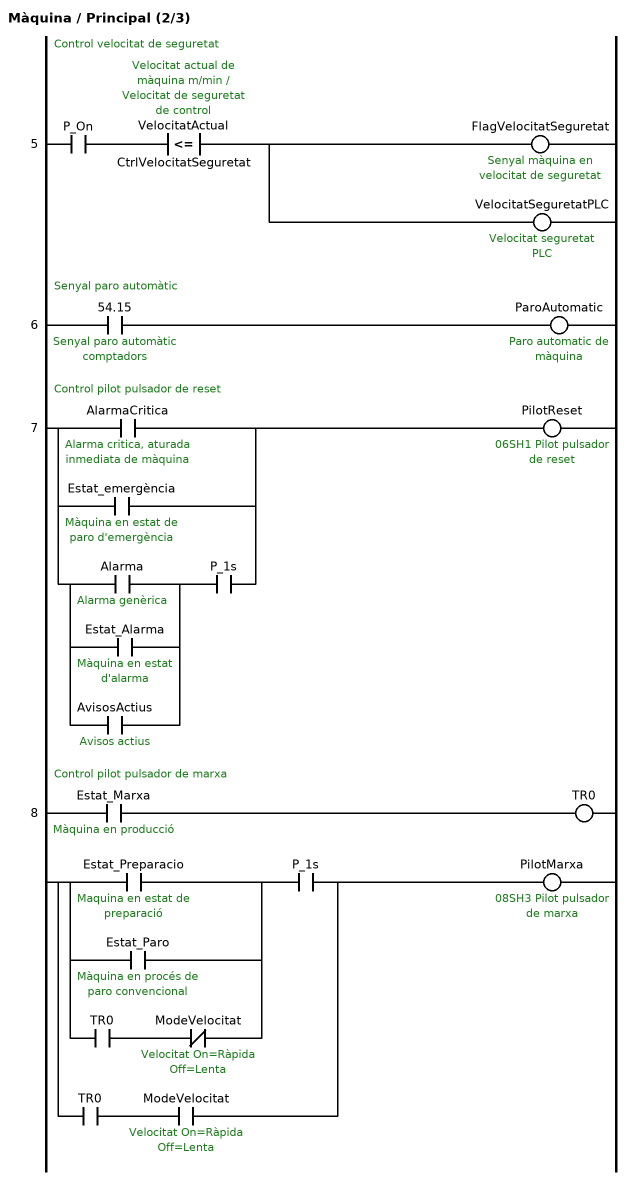
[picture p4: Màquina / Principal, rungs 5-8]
; rung 5: Control velocitat de seguretat
LD P_On
AND<=S(317) VelocitatActual CtrlVelocitatSeguretat  ; Velocitat actual de màquina m/min, Velocitat de seguretat de control
OUT FlagVelocitatSeguretat  ; Senyal màquina en velocitat de seguretat
OUT VelocitatSeguretatPLC  ; Velocitat seguretat PLC
; rung 6: Senyal paro automàtic
LD 54.15  ; Senyal paro automàtic comptadors
OUT ParoAutomatic  ; Paro automatic de màquina
; rung 7: Control pilot pulsador de reset
LD AlarmaCritica  ; Alarma critica, aturada inmediata de màquina
OR Estat_emergència  ; Màquina en estat de paro d'emergència
LD Alarma  ; Alarma genèrica
OR Estat_Alarma  ; Màquina en estat d'alarma
OR AvisosActius  ; Avisos actius
AND P_1s
ORLD
OUT PilotReset  ; 06SH1 Pilot pulsador de reset
; rung 8: Control pilot pulsador de marxa
LD Estat_Preparacio  ; Maquina en estat de preparació
OR Estat_Paro  ; Màquina en procés de paro convencional
LD Estat_Marxa  ; Màquina en producció
OUT TR0
ANDNOT ModeVelocitat  ; Velocitat On=Ràpida Off=Lenta
ORLD
AND P_1s
LD TR0
AND ModeVelocitat  ; Velocitat On=Ràpida Off=Lenta
ORLD
OUT PilotMarxa  ; 08SH3 Pilot pulsador de marxa

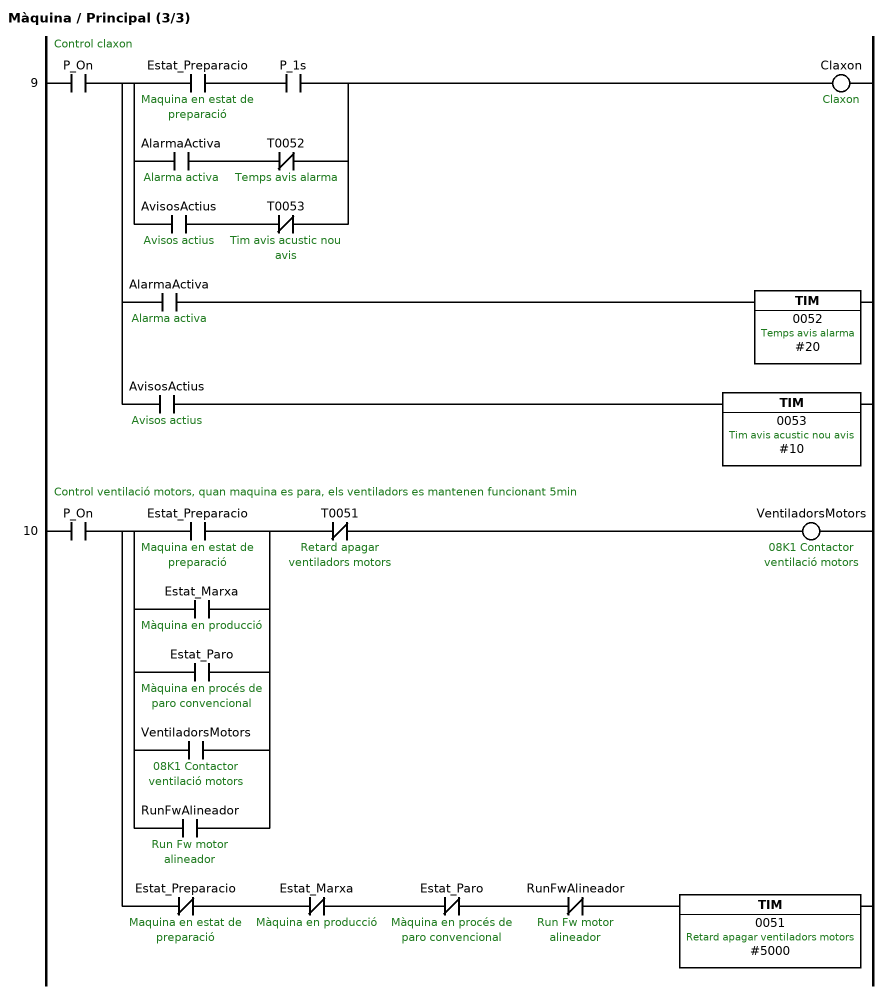
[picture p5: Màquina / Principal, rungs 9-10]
; rung 9: Control claxon
LD P_On
OUT TR0
LD Estat_Preparacio  ; Maquina en estat de preparació
AND P_1s
LD AlarmaActiva  ; Alarma activa
ANDNOT T0052  ; Temps avis alarma
ORLD
LD AvisosActius  ; Avisos actius
ANDNOT T0053  ; Tim avis acustic nou avis
ORLD
ANDLD
OUT Claxon  ; Claxon
LD TR0
AND AlarmaActiva  ; Alarma activa
TIM 0052 #20  ; Temps avis alarma
LD TR0
AND AvisosActius  ; Avisos actius
TIM 0053 #10  ; Tim avis acustic nou avis
; rung 10: Control ventilació motors, quan maquina es para, els ventiladors es mantenen funcionant 5min
LD P_On
OUT TR0
LD Estat_Preparacio  ; Maquina en estat de preparació
OR Estat_Marxa  ; Màquina en producció
OR Estat_Paro  ; Màquina en procés de paro convencional
OR VentiladorsMotors  ; 08K1 Contactor ventilació motors
OR RunFwAlineador  ; Run Fw motor alineador
ANDLD
ANDNOT T0051  ; Retard apagar ventiladors motors
OUT VentiladorsMotors  ; 08K1 Contactor ventilació motors
LD TR0
ANDNOT Estat_Preparacio  ; Maquina en estat de preparació
ANDNOT Estat_Marxa  ; Màquina en producció
ANDNOT Estat_Paro  ; Màquina en procés de paro convencional
ANDNOT RunFwAlineador  ; Run Fw motor alineador
TIM 0051 #5000  ; Retard apagar ventiladors motors

### Section Alarmes

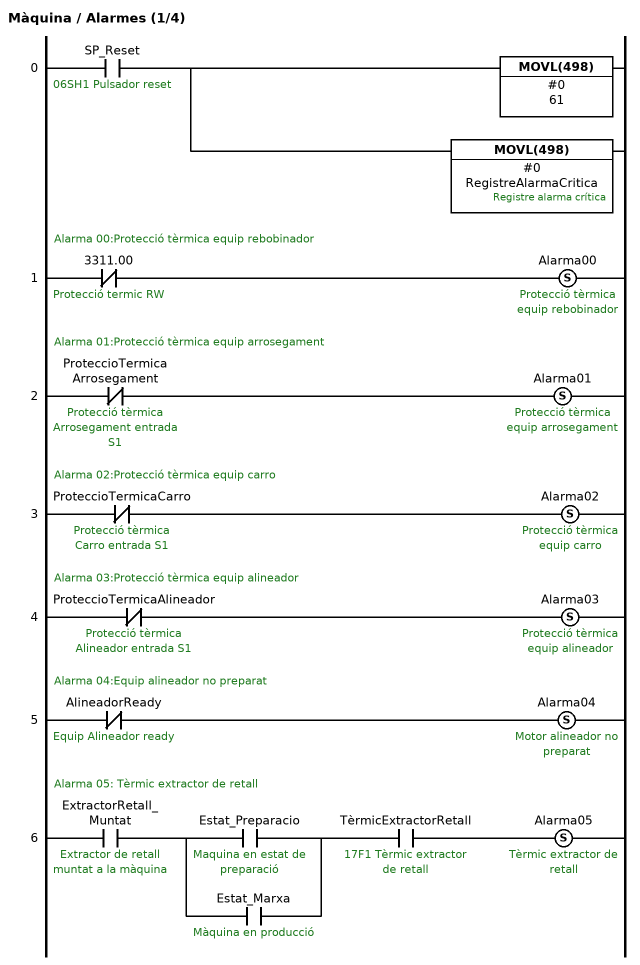
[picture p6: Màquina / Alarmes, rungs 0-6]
; rung 0
LD SP_Reset  ; 06SH1 Pulsador reset
MOVL(498) #0 61
MOVL(498) #0 RegistreAlarmaCritica  ; Registre alarma crítica
; rung 1: Alarma 00:Protecció tèrmica equip rebobinador
LDNOT 3311.00  ; Protecció termic RW
SET Alarma00  ; Protecció tèrmica equip rebobinador
; rung 2: Alarma 01:Protecció tèrmica equip arrosegament
LDNOT ProteccioTermicaArrosegament  ; Protecció tèrmica Arrosegament entrada S1
SET Alarma01  ; Protecció tèrmica equip arrosegament
; rung 3: Alarma 02:Protecció tèrmica equip carro
LDNOT ProteccioTermicaCarro  ; Protecció tèrmica Carro entrada S1
SET Alarma02  ; Protecció tèrmica equip carro
; rung 4: Alarma 03:Protecció tèrmica equip alineador
LDNOT ProteccioTermicaAlineador  ; Protecció tèrmica Alineador entrada S1
SET Alarma03  ; Protecció tèrmica equip alineador
; rung 5: Alarma 04:Equip alineador no preparat
LDNOT AlineadorReady  ; Equip Alineador ready
SET Alarma04  ; Motor alineador no preparat
; rung 6: Alarma 05: Tèrmic extractor de retall
LD ExtractorRetall_Muntat  ; Extractor de retall muntat a la màquina
LD Estat_Preparacio  ; Maquina en estat de preparació
OR Estat_Marxa  ; Màquina en producció
ANDLD
AND TèrmicExtractorRetall  ; 17F1 Tèrmic extractor de retall
SET Alarma05  ; Tèrmic extractor de retall

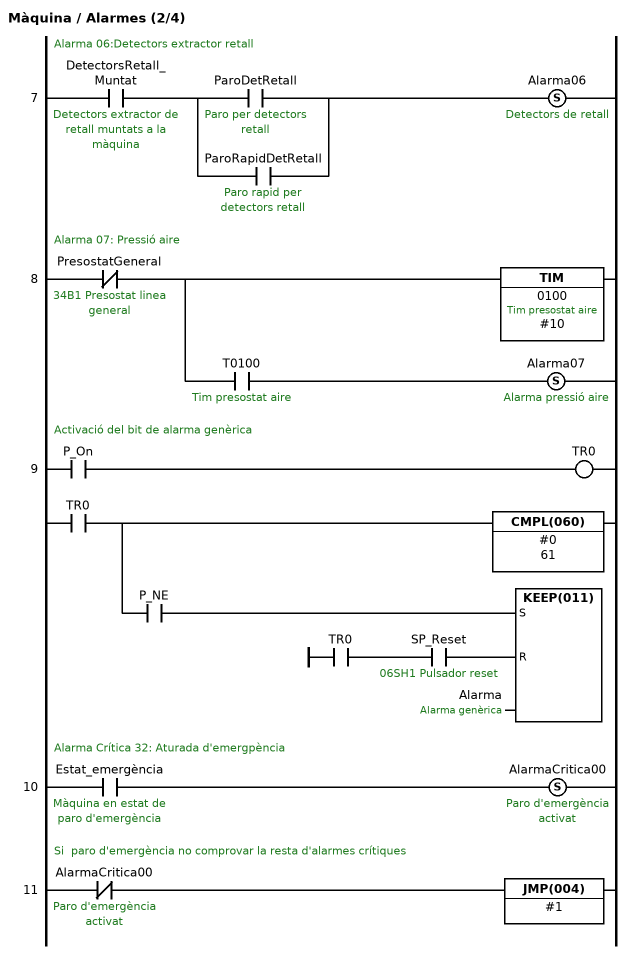
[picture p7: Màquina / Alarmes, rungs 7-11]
; rung 7: Alarma 06:Detectors extractor retall
LD DetectorsRetall_Muntat  ; Detectors extractor de retall muntats a la màquina
LD ParoDetRetall  ; Paro per detectors retall
OR ParoRapidDetRetall  ; Paro rapid per detectors retall
ANDLD
SET Alarma06  ; Detectors de retall
; rung 8: Alarma 07: Pressió aire
LDNOT PresostatGeneral  ; 34B1 Presostat linea general
TIM 0100 #10  ; Tim presostat aire
AND T0100  ; Tim presostat aire
SET Alarma07  ; Alarma pressió aire
; rung 9: Activació del bit de alarma genèrica
LD P_On
OUT TR0
CMPL(060) #0 61
AND P_NE
LD TR0
AND SP_Reset  ; 06SH1 Pulsador reset
KEEP(011) Alarma  ; Alarma genèrica
; rung 10: Alarma Crítica 32: Aturada d'emergpència
LD Estat_emergència  ; Màquina en estat de paro d'emergència
SET AlarmaCritica00  ; Paro d'emergència activat
; rung 11: Si  paro d'emergència no comprovar la resta d'alarmes crítiques
LDNOT AlarmaCritica00  ; Paro d'emergència activat
JMP(004) #1

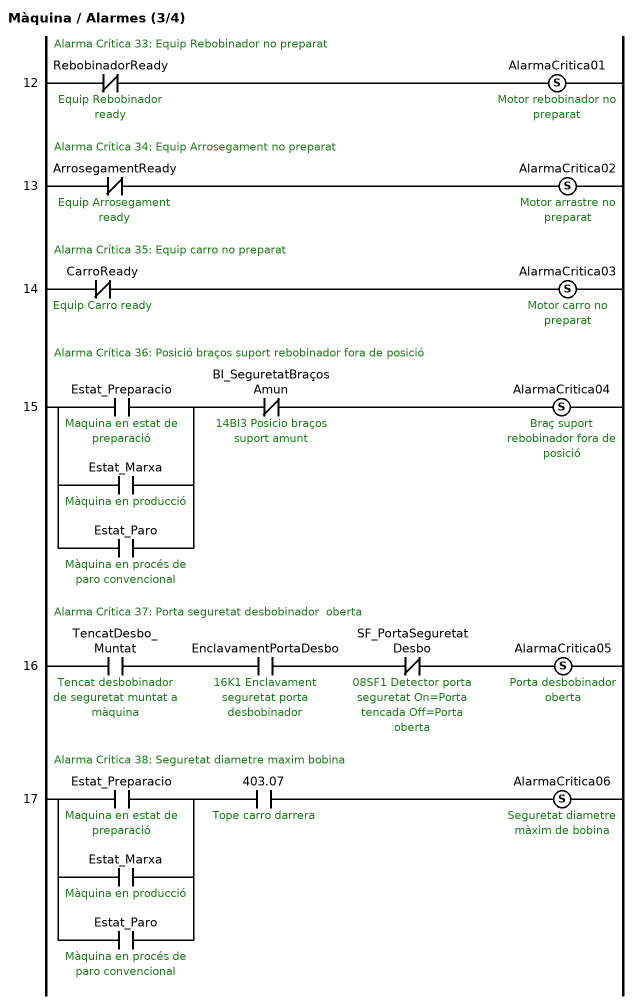
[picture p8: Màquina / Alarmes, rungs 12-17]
; rung 12: Alarma Crítica 33: Equip Rebobinador no preparat
LDNOT RebobinadorReady  ; Equip Rebobinador ready
SET AlarmaCritica01  ; Motor rebobinador no preparat
; rung 13: Alarma Crítica 34: Equip Arrosegament no preparat
LDNOT ArrosegamentReady  ; Equip Arrosegament ready
SET AlarmaCritica02  ; Motor arrastre no preparat
; rung 14: Alarma Crítica 35: Equip carro no preparat
LDNOT CarroReady  ; Equip Carro ready
SET AlarmaCritica03  ; Motor carro no preparat
; rung 15: Alarma Crítica 36: Posició braços suport rebobinador fora de posició
LD Estat_Preparacio  ; Maquina en estat de preparació
OR Estat_Marxa  ; Màquina en producció
OR Estat_Paro  ; Màquina en procés de paro convencional
ANDNOT BI_SeguretatBraçosAmun  ; 14BI3 Posicio braços suport amunt
SET AlarmaCritica04  ; Braç suport rebobinador fora de posició
; rung 16: Alarma Crítica 37: Porta seguretat desbobinador  oberta
LD TencatDesbo_Muntat  ; Tencat desbobinador de seguretat muntat a màquina
AND EnclavamentPortaDesbo  ; 16K1 Enclavament seguretat porta desbobinador
ANDNOT SF_PortaSeguretatDesbo  ; 08SF1 Detector porta seguretat On=Porta tencada Off=Porta oberta
SET AlarmaCritica05  ; Porta desbobinador oberta
; rung 17: Alarma Critica 38: Seguretat diametre maxim bobina
LD Estat_Preparacio  ; Maquina en estat de preparació
OR Estat_Marxa  ; Màquina en producció
OR Estat_Paro  ; Màquina en procés de paro convencional
AND 403.07  ; Tope carro darrera
SET AlarmaCritica06  ; Seguretat diametre màxim de bobina

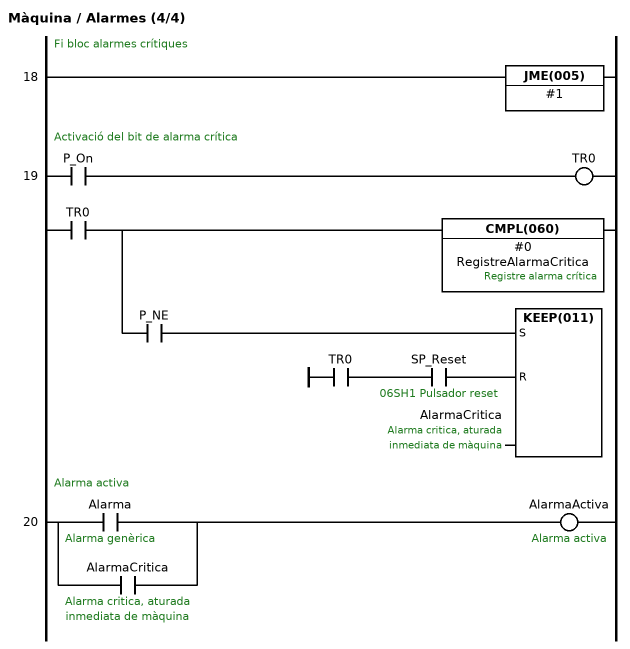
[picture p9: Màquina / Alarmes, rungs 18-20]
; rung 18: Fi bloc alarmes crítiques
JME(005) #1
; rung 19: Activació del bit de alarma crítica
LD P_On
OUT TR0
CMPL(060) #0 RegistreAlarmaCritica  ; Registre alarma crítica
AND P_NE
LD TR0
AND SP_Reset  ; 06SH1 Pulsador reset
KEEP(011) AlarmaCritica  ; Alarma critica, aturada inmediata de màquina
; rung 20: Alarma activa
LD Alarma  ; Alarma genèrica
OR AlarmaCritica  ; Alarma critica, aturada inmediata de màquina
OUT AlarmaActiva  ; Alarma activa

### Section Avisos

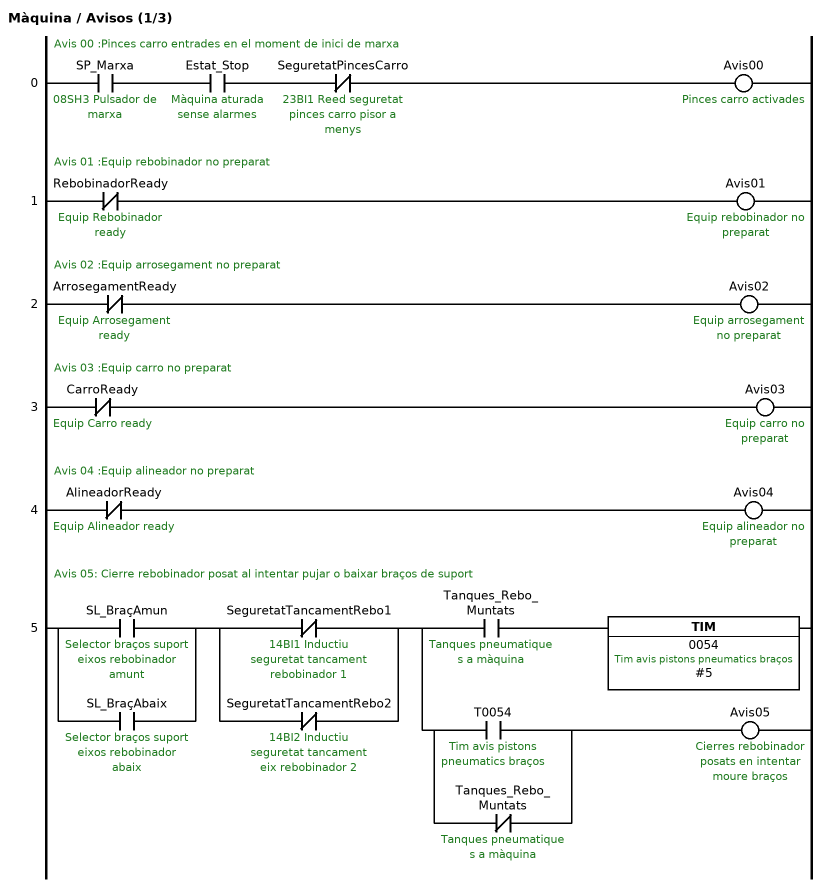
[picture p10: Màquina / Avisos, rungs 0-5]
; rung 0: Avis 00 :Pinces carro entrades en el moment de inici de marxa
LD SP_Marxa  ; 08SH3 Pulsador de marxa
AND Estat_Stop  ; Màquina aturada sense alarmes
ANDNOT SeguretatPincesCarro  ; 23BI1 Reed seguretat pinces carro pisor a menys
OUT Avis00  ; Pinces carro activades
; rung 1: Avis 01 :Equip rebobinador no preparat
LDNOT RebobinadorReady  ; Equip Rebobinador ready
OUT Avis01  ; Equip rebobinador no preparat
; rung 2: Avis 02 :Equip arrosegament no preparat
LDNOT ArrosegamentReady  ; Equip Arrosegament ready
OUT Avis02  ; Equip arrosegament no preparat
; rung 3: Avis 03 :Equip carro no preparat
LDNOT CarroReady  ; Equip Carro ready
OUT Avis03  ; Equip carro no preparat
; rung 4: Avis 04 :Equip alineador no preparat
LDNOT AlineadorReady  ; Equip Alineador ready
OUT Avis04  ; Equip alineador no preparat
; rung 5: Avis 05: Cierre rebobinador posat al intentar pujar o baixar braços de suport
LD SL_BraçAmun  ; Selector braços suport eixos rebobinador amunt
OR SL_BraçAbaix  ; Selector braços suport eixos rebobinador abaix
LDNOT SeguretatTancamentRebo1  ; 14BI1 Inductiu seguretat tancament rebobinador 1
ORNOT SeguretatTancamentRebo2  ; 14BI2 Inductiu seguretat tancament eix rebobinador 2
ANDLD
OUT TR0
AND Tanques_Rebo_Muntats  ; Tanques pneumatiques a màquina
TIM 0054 #5  ; Tim avis pistons pneumatics braços
LD TR0
LD T0054  ; Tim avis pistons pneumatics braços
ORNOT Tanques_Rebo_Muntats  ; Tanques pneumatiques a màquina
ANDLD
OUT Avis05  ; Cierres rebobinador posats en intentar moure braços

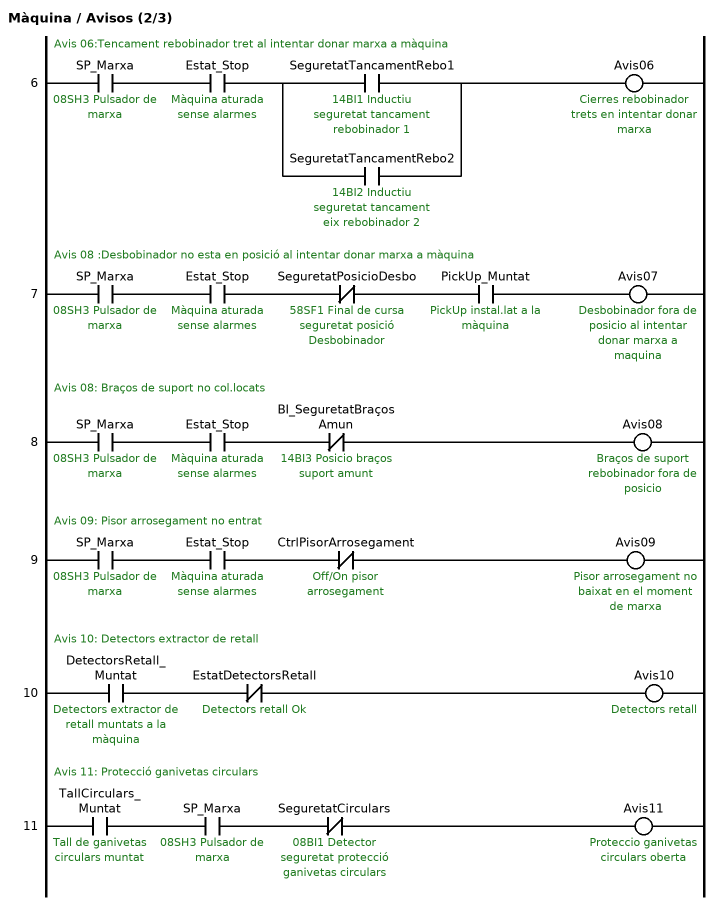
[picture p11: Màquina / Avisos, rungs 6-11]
; rung 6: Avis 06:Tencament rebobinador tret al intentar donar marxa a màquina
LD SP_Marxa  ; 08SH3 Pulsador de marxa
AND Estat_Stop  ; Màquina aturada sense alarmes
LD SeguretatTancamentRebo1  ; 14BI1 Inductiu seguretat tancament rebobinador 1
OR SeguretatTancamentRebo2  ; 14BI2 Inductiu seguretat tancament eix rebobinador 2
ANDLD
OUT Avis06  ; Cierres rebobinador trets en intentar donar marxa
; rung 7: Avis 08 :Desbobinador no esta en posició al intentar donar marxa a màquina
LD SP_Marxa  ; 08SH3 Pulsador de marxa
AND Estat_Stop  ; Màquina aturada sense alarmes
ANDNOT SeguretatPosicioDesbo  ; 58SF1 Final de cursa seguretat posició Desbobinador
AND PickUp_Muntat  ; PickUp instal.lat a la màquina
OUT Avis07  ; Desbobinador fora de posicio al intentar donar marxa a maquina
; rung 8: Avis 08: Braços de suport no col.locats
LD SP_Marxa  ; 08SH3 Pulsador de marxa
AND Estat_Stop  ; Màquina aturada sense alarmes
ANDNOT BI_SeguretatBraçosAmun  ; 14BI3 Posicio braços suport amunt
OUT Avis08  ; Braços de suport rebobinador fora de posicio
; rung 9: Avis 09: Pisor arrosegament no entrat
LD SP_Marxa  ; 08SH3 Pulsador de marxa
AND Estat_Stop  ; Màquina aturada sense alarmes
ANDNOT CtrlPisorArrosegament  ; Off/On pisor arrosegament
OUT Avis09  ; Pisor arrosegament no baixat en el moment de marxa
; rung 10: Avis 10: Detectors extractor de retall
LD DetectorsRetall_Muntat  ; Detectors extractor de retall muntats a la màquina
ANDNOT EstatDetectorsRetall  ; Detectors retall Ok
OUT Avis10  ; Detectors retall
; rung 11: Avis 11: Protecció ganivetas circulars
LD TallCirculars_Muntat  ; Tall de ganivetas circulars muntat
AND SP_Marxa  ; 08SH3 Pulsador de marxa
ANDNOT SeguretatCirculars  ; 08BI1 Detector seguretat protecció ganivetas circulars
OUT Avis11  ; Proteccio ganivetas circulars oberta

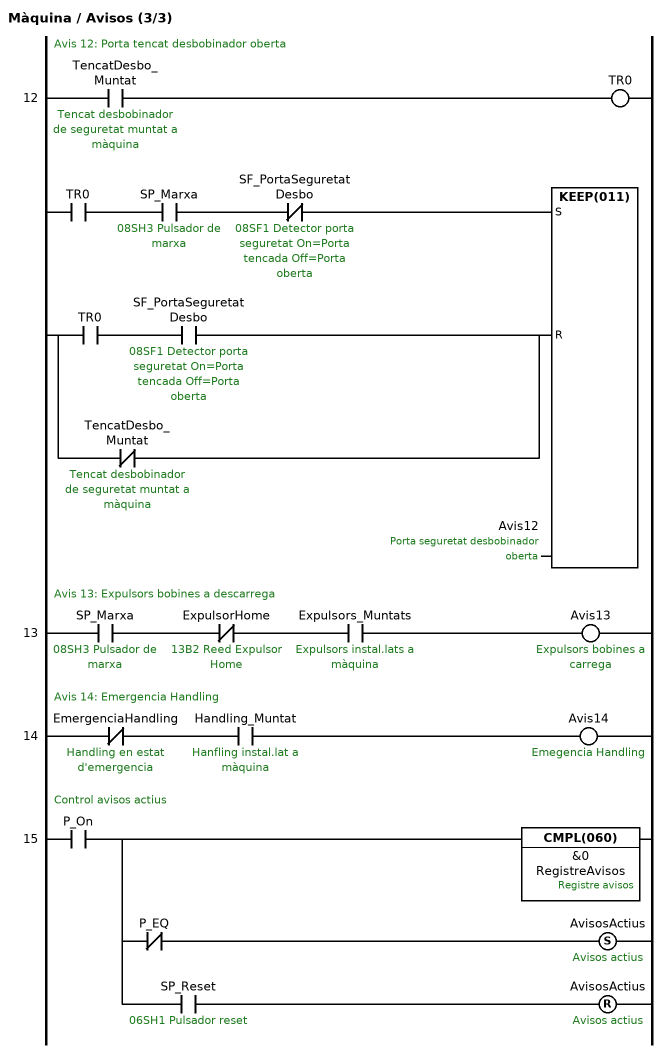
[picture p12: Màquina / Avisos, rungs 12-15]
; rung 12: Avis 12: Porta tencat desbobinador oberta
LD TencatDesbo_Muntat  ; Tencat desbobinador de seguretat muntat a màquina
OUT TR0
AND SP_Marxa  ; 08SH3 Pulsador de marxa
ANDNOT SF_PortaSeguretatDesbo  ; 08SF1 Detector porta seguretat On=Porta tencada Off=Porta oberta
LD TR0
AND SF_PortaSeguretatDesbo  ; 08SF1 Detector porta seguretat On=Porta tencada Off=Porta oberta
ORNOT TencatDesbo_Muntat  ; Tencat desbobinador de seguretat muntat a màquina
KEEP(011) Avis12  ; Porta seguretat desbobinador oberta
; rung 13: Avis 13: Expulsors bobines a descarrega
LD SP_Marxa  ; 08SH3 Pulsador de marxa
ANDNOT ExpulsorHome  ; 13B2 Reed Expulsor Home
AND Expulsors_Muntats  ; Expulsors instal.lats a màquina
OUT Avis13  ; Expulsors bobines a carrega
; rung 14: Avis 14: Emergencia Handling
LDNOT EmergenciaHandling  ; Handling en estat d'emergencia
AND Handling_Muntat  ; Hanfling instal.lat a màquina
OUT Avis14  ; Emegencia Handling
; rung 15: Control avisos actius
LD P_On
OUT TR0
CMPL(060) &0 RegistreAvisos  ; Registre avisos
ANDNOT P_EQ
SET AvisosActius  ; Avisos actius
LD TR0
AND SP_Reset  ; 06SH1 Pulsador reset
RSET AvisosActius  ; Avisos actius

### Section Velocitat

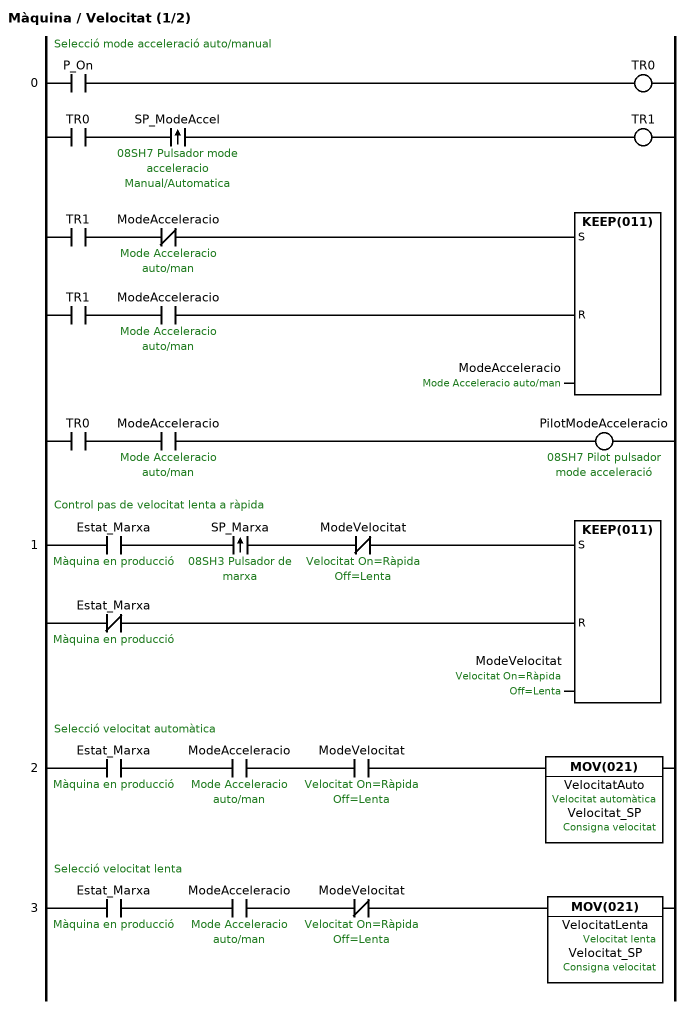
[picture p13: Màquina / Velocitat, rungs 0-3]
; rung 0: Selecció mode acceleració auto/manual
LD P_On
OUT TR0
@AND SP_ModeAccel  ; 08SH7 Pulsador mode acceleracio Manual/Automatica
OUT TR1
ANDNOT ModeAcceleracio  ; Mode Acceleracio auto/man
LD TR1
AND ModeAcceleracio  ; Mode Acceleracio auto/man
KEEP(011) ModeAcceleracio  ; Mode Acceleracio auto/man
LD TR0
AND ModeAcceleracio  ; Mode Acceleracio auto/man
OUT PilotModeAcceleracio  ; 08SH7 Pilot pulsador mode acceleració
; rung 1: Control pas de velocitat lenta a ràpida
LD Estat_Marxa  ; Màquina en producció
@AND SP_Marxa  ; 08SH3 Pulsador de marxa
ANDNOT ModeVelocitat  ; Velocitat On=Ràpida Off=Lenta
LDNOT Estat_Marxa  ; Màquina en producció
KEEP(011) ModeVelocitat  ; Velocitat On=Ràpida Off=Lenta
; rung 2: Selecció velocitat automàtica
LD Estat_Marxa  ; Màquina en producció
AND ModeAcceleracio  ; Mode Acceleracio auto/man
AND ModeVelocitat  ; Velocitat On=Ràpida Off=Lenta
MOV(021) VelocitatAuto Velocitat_SP  ; Velocitat automàtica, Consigna velocitat
; rung 3: Selecció velocitat lenta
LD Estat_Marxa  ; Màquina en producció
AND ModeAcceleracio  ; Mode Acceleracio auto/man
ANDNOT ModeVelocitat  ; Velocitat On=Ràpida Off=Lenta
MOV(021) VelocitatLenta Velocitat_SP  ; Velocitat lenta, Consigna velocitat

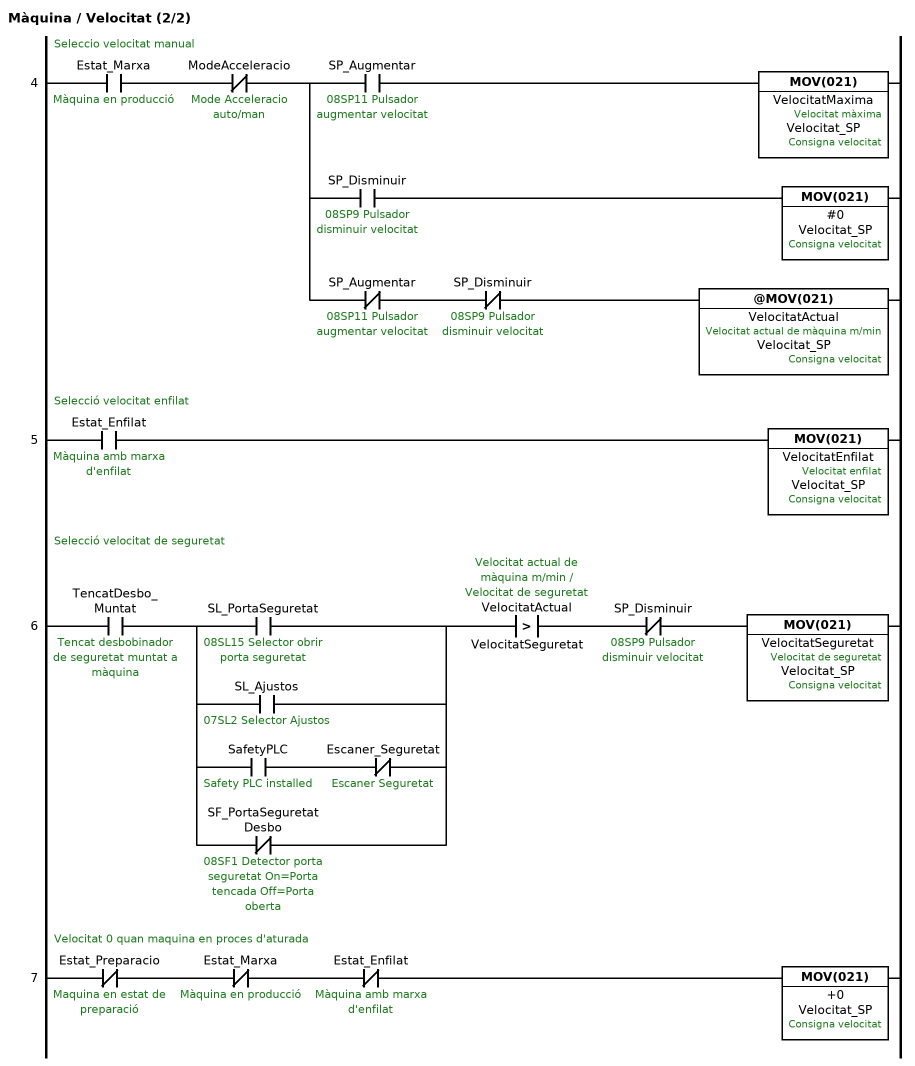
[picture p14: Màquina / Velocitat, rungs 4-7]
; rung 4: Seleccio velocitat manual
LD Estat_Marxa  ; Màquina en producció
ANDNOT ModeAcceleracio  ; Mode Acceleracio auto/man
OUT TR0
AND SP_Augmentar  ; 08SP11 Pulsador augmentar velocitat
MOV(021) VelocitatMaxima Velocitat_SP  ; Velocitat màxima, Consigna velocitat
LD TR0
AND SP_Disminuir  ; 08SP9 Pulsador disminuir velocitat
MOV(021) #0 Velocitat_SP  ; Consigna velocitat
LD TR0
ANDNOT SP_Augmentar  ; 08SP11 Pulsador augmentar velocitat
ANDNOT SP_Disminuir  ; 08SP9 Pulsador disminuir velocitat
@MOV(021) VelocitatActual Velocitat_SP  ; Velocitat actual de màquina m/min, Consigna velocitat
; rung 5: Selecció velocitat enfilat
LD Estat_Enfilat  ; Màquina amb marxa d'enfilat
MOV(021) VelocitatEnfilat Velocitat_SP  ; Velocitat enfilat, Consigna velocitat
; rung 6: Selecció velocitat de seguretat
LD TencatDesbo_Muntat  ; Tencat desbobinador de seguretat muntat a màquina
LD SL_PortaSeguretat  ; 08SL15 Selector obrir porta seguretat
OR SL_Ajustos  ; 07SL2 Selector Ajustos
LD SafetyPLC  ; Safety PLC installed
ANDNOT Escaner_Seguretat  ; Escaner Seguretat
ORLD
ORNOT SF_PortaSeguretatDesbo  ; 08SF1 Detector porta seguretat On=Porta tencada Off=Porta oberta
ANDLD
AND>S(322) VelocitatActual VelocitatSeguretat  ; Velocitat actual de màquina m/min, Velocitat de seguretat
ANDNOT SP_Disminuir  ; 08SP9 Pulsador disminuir velocitat
MOV(021) VelocitatSeguretat Velocitat_SP  ; Velocitat de seguretat, Consigna velocitat
; rung 7: Velocitat 0 quan maquina en proces d'aturada
LDNOT Estat_Preparacio  ; Maquina en estat de preparació
ANDNOT Estat_Marxa  ; Màquina en producció
ANDNOT Estat_Enfilat  ; Màquina amb marxa d'enfilat
MOV(021) +0 Velocitat_SP  ; Consigna velocitat

### Section Comptadors

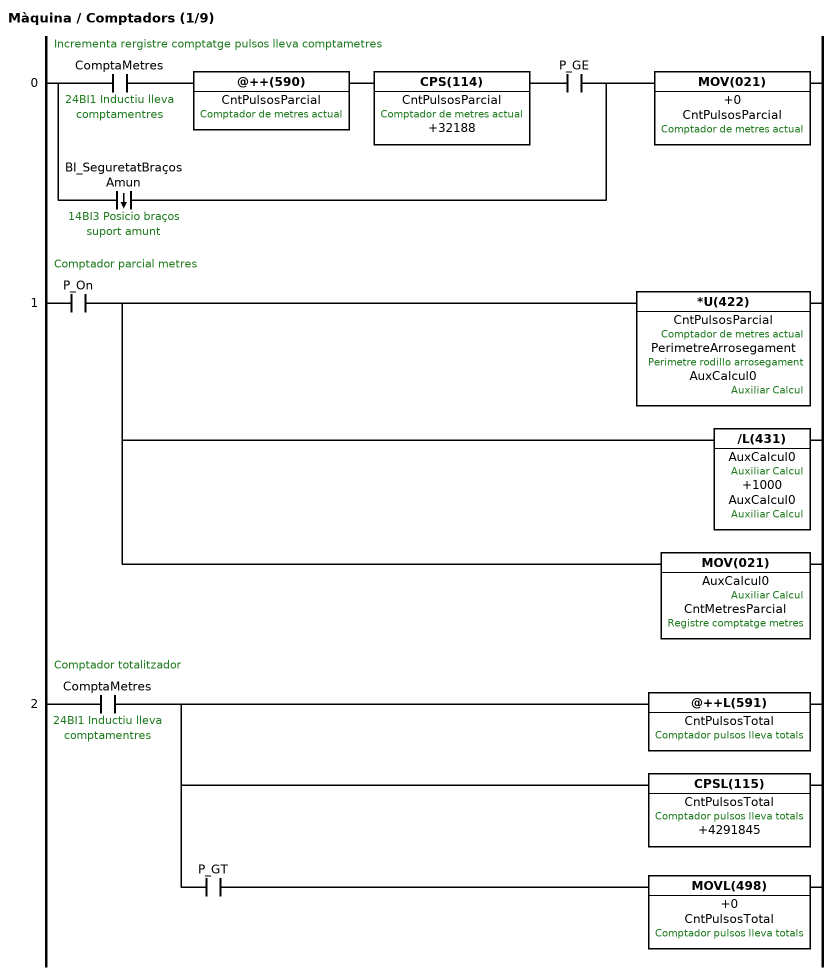
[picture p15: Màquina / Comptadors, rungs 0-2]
; rung 0: Incrementa rergistre comptatge pulsos lleva comptametres
LD ComptaMetres  ; 24BI1 Inductiu lleva comptamentres
@++(590) CntPulsosParcial  ; Comptador de metres actual
CPS(114) CntPulsosParcial +32188  ; Comptador de metres actual
AND P_GE
%OR BI_SeguretatBraçosAmun  ; 14BI3 Posicio braços suport amunt
MOV(021) +0 CntPulsosParcial  ; Comptador de metres actual
; rung 1: Comptador parcial metres
LD P_On
*U(422) CntPulsosParcial PerimetreArrosegament AuxCalcul0  ; Comptador de metres actual, Perimetre rodillo arrosegament, Auxiliar Calcul
/L(431) AuxCalcul0 +1000 AuxCalcul0  ; Auxiliar Calcul
MOV(021) AuxCalcul0 CntMetresParcial  ; Auxiliar Calcul, Registre comptatge metres
; rung 2: Comptador totalitzador
LD ComptaMetres  ; 24BI1 Inductiu lleva comptamentres
@++L(591) CntPulsosTotal  ; Comptador pulsos lleva totals
CPSL(115) CntPulsosTotal +4291845  ; Comptador pulsos lleva totals
AND P_GT
MOVL(498) +0 CntPulsosTotal  ; Comptador pulsos lleva totals

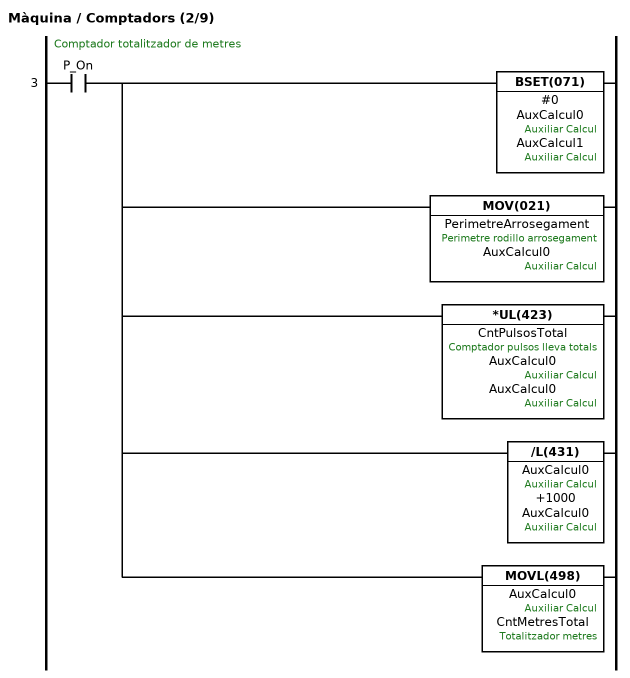
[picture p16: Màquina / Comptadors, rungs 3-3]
; rung 3: Comptador totalitzador de metres
LD P_On
BSET(071) #0 AuxCalcul0 AuxCalcul1  ; Auxiliar Calcul
MOV(021) PerimetreArrosegament AuxCalcul0  ; Perimetre rodillo arrosegament, Auxiliar Calcul
*UL(423) CntPulsosTotal AuxCalcul0 AuxCalcul0  ; Comptador pulsos lleva totals, Auxiliar Calcul
/L(431) AuxCalcul0 +1000 AuxCalcul0  ; Auxiliar Calcul
MOVL(498) AuxCalcul0 CntMetresTotal  ; Auxiliar Calcul, Totalitzador metres

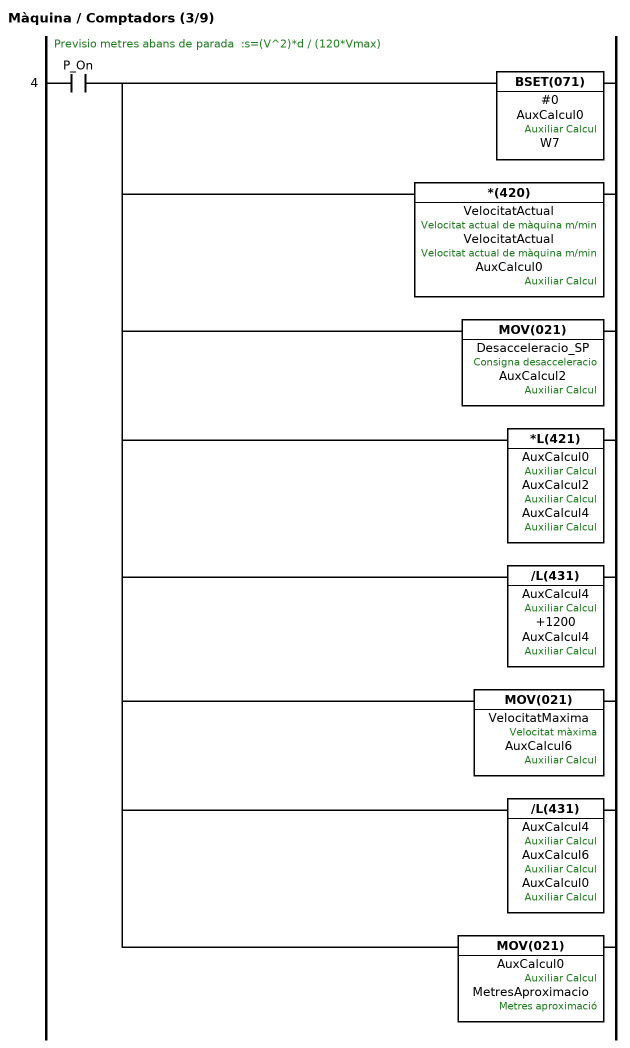
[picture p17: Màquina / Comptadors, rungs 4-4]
; rung 4: Previsio metres abans de parada  :s=(V^2)*d / (120*Vmax)
LD P_On
BSET(071) #0 AuxCalcul0 W7  ; Auxiliar Calcul
*(420) VelocitatActual VelocitatActual AuxCalcul0  ; Velocitat actual de màquina m/min, Auxiliar Calcul
MOV(021) Desacceleracio_SP AuxCalcul2  ; Consigna desacceleracio, Auxiliar Calcul
*L(421) AuxCalcul0 AuxCalcul2 AuxCalcul4  ; Auxiliar Calcul
/L(431) AuxCalcul4 +1200 AuxCalcul4  ; Auxiliar Calcul
MOV(021) VelocitatMaxima AuxCalcul6  ; Velocitat màxima, Auxiliar Calcul
/L(431) AuxCalcul4 AuxCalcul6 AuxCalcul0  ; Auxiliar Calcul
MOV(021) AuxCalcul0 MetresAproximacio  ; Auxiliar Calcul, Metres aproximació

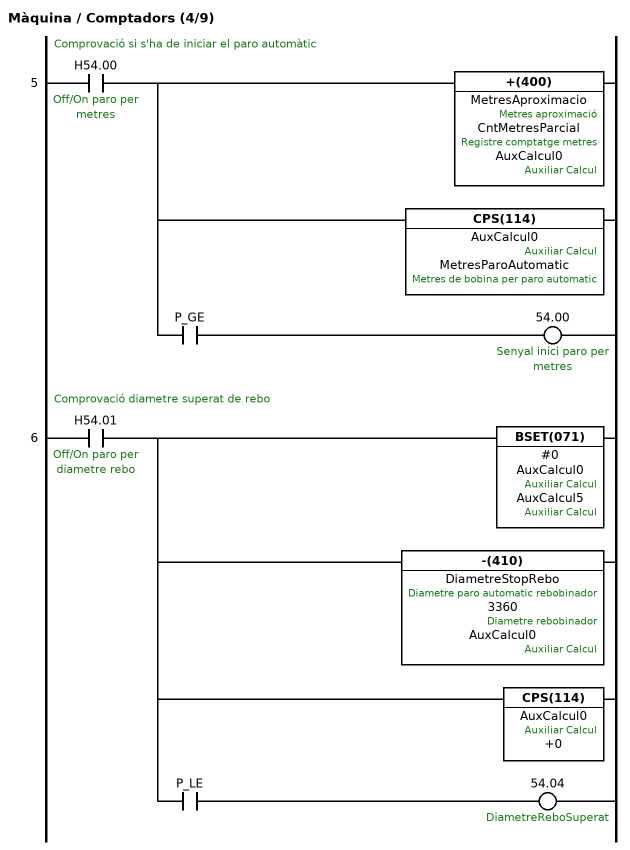
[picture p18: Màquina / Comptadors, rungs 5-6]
; rung 5: Comprovació si s'ha de iniciar el paro automàtic
LD H54.00  ; Off/On paro per metres
+(400) MetresAproximacio CntMetresParcial AuxCalcul0  ; Metres aproximació, Registre comptatge metres, Auxiliar Calcul
CPS(114) AuxCalcul0 MetresParoAutomatic  ; Auxiliar Calcul, Metres de bobina per paro automatic
AND P_GE
OUT 54.00  ; Senyal inici paro per metres
; rung 6: Comprovació diametre superat de rebo
LD H54.01  ; Off/On paro per diametre rebo
BSET(071) #0 AuxCalcul0 AuxCalcul5  ; Auxiliar Calcul
-(410) DiametreStopRebo 3360 AuxCalcul0  ; Diametre paro automatic rebobinador, Diametre rebobinador, Auxiliar Calcul
CPS(114) AuxCalcul0 +0  ; Auxiliar Calcul
AND P_LE
OUT 54.04  ; DiametreReboSuperat

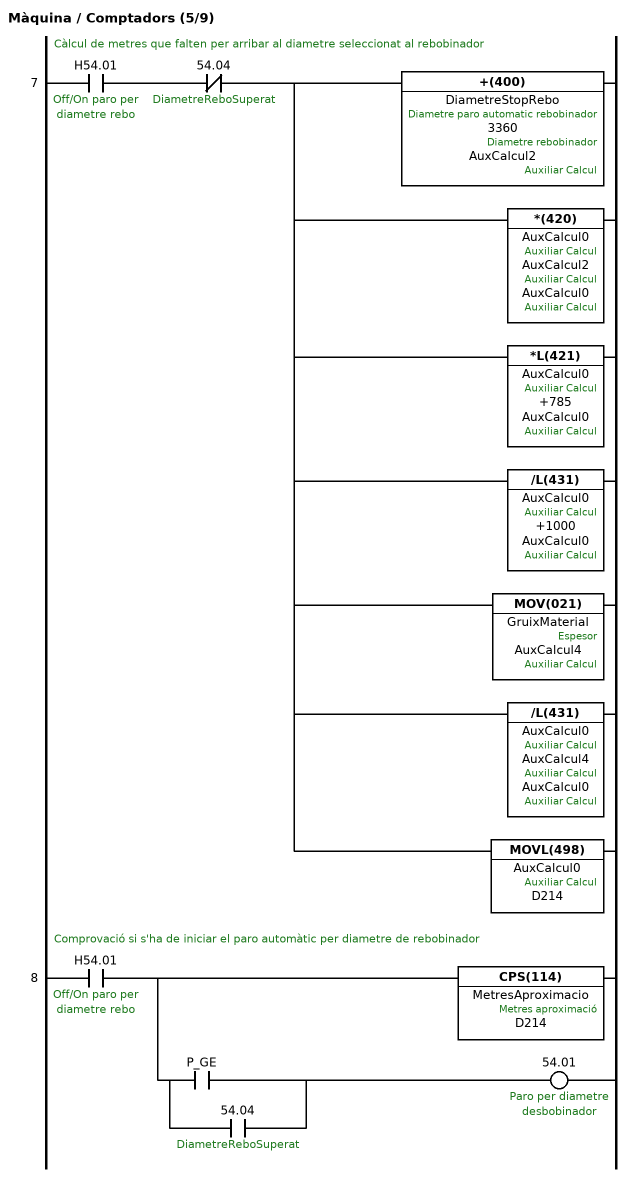
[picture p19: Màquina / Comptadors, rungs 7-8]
; rung 7: Càlcul de metres que falten per arribar al diametre seleccionat al rebobinador
LD H54.01  ; Off/On paro per diametre rebo
ANDNOT 54.04  ; DiametreReboSuperat
+(400) DiametreStopRebo 3360 AuxCalcul2  ; Diametre paro automatic rebobinador, Diametre rebobinador, Auxiliar Calcul
*(420) AuxCalcul0 AuxCalcul2 AuxCalcul0  ; Auxiliar Calcul
*L(421) AuxCalcul0 +785 AuxCalcul0  ; Auxiliar Calcul
/L(431) AuxCalcul0 +1000 AuxCalcul0  ; Auxiliar Calcul
MOV(021) GruixMaterial AuxCalcul4  ; Espesor, Auxiliar Calcul
/L(431) AuxCalcul0 AuxCalcul4 AuxCalcul0  ; Auxiliar Calcul
MOVL(498) AuxCalcul0 D214  ; Auxiliar Calcul
; rung 8: Comprovació si s'ha de iniciar el paro automàtic per diametre de rebobinador
LD H54.01  ; Off/On paro per diametre rebo
CPS(114) MetresAproximacio D214  ; Metres aproximació
LD P_GE
OR 54.04  ; DiametreReboSuperat
ANDLD
OUT 54.01  ; Paro per diametre desbobinador

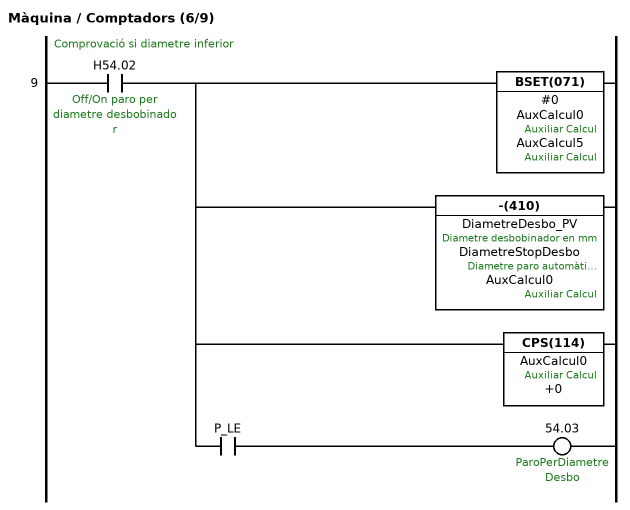
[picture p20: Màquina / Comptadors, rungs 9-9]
; rung 9: Comprovació si diametre inferior
LD H54.02  ; Off/On paro per diametre desbobinador
BSET(071) #0 AuxCalcul0 AuxCalcul5  ; Auxiliar Calcul
-(410) DiametreDesbo_PV DiametreStopDesbo AuxCalcul0  ; Diametre desbobinador en mm, Diametre paro automàtic desbobinador, Auxiliar Calcul
CPS(114) AuxCalcul0 +0  ; Auxiliar Calcul
AND P_LE
OUT 54.03  ; ParoPerDiametreDesbo

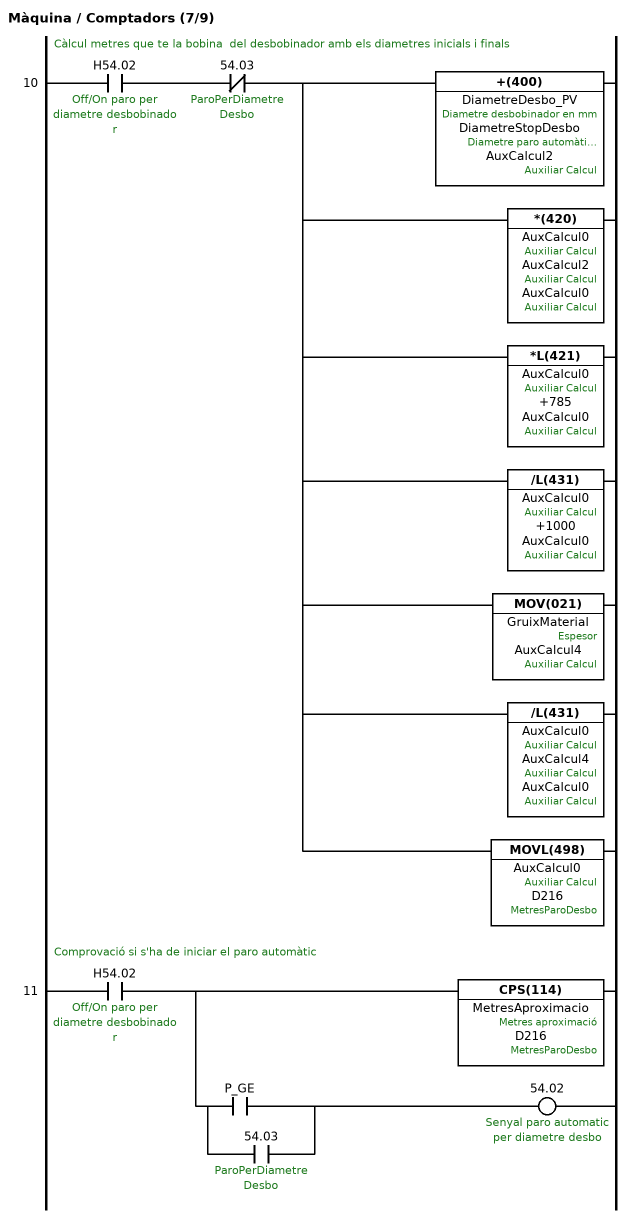
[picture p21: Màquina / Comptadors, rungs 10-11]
; rung 10: Càlcul metres que te la bobina  del desbobinador amb els diametres inicials i finals
LD H54.02  ; Off/On paro per diametre desbobinador
ANDNOT 54.03  ; ParoPerDiametreDesbo
+(400) DiametreDesbo_PV DiametreStopDesbo AuxCalcul2  ; Diametre desbobinador en mm, Diametre paro automàtic desbobinador, Auxiliar Calcul
*(420) AuxCalcul0 AuxCalcul2 AuxCalcul0  ; Auxiliar Calcul
*L(421) AuxCalcul0 +785 AuxCalcul0  ; Auxiliar Calcul
/L(431) AuxCalcul0 +1000 AuxCalcul0  ; Auxiliar Calcul
MOV(021) GruixMaterial AuxCalcul4  ; Espesor, Auxiliar Calcul
/L(431) AuxCalcul0 AuxCalcul4 AuxCalcul0  ; Auxiliar Calcul
MOVL(498) AuxCalcul0 D216  ; Auxiliar Calcul, MetresParoDesbo
; rung 11: Comprovació si s'ha de iniciar el paro automàtic
LD H54.02  ; Off/On paro per diametre desbobinador
CPS(114) MetresAproximacio D216  ; Metres aproximació, MetresParoDesbo
LD P_GE
OR 54.03  ; ParoPerDiametreDesbo
ANDLD
OUT 54.02  ; Senyal paro automatic per diametre desbo

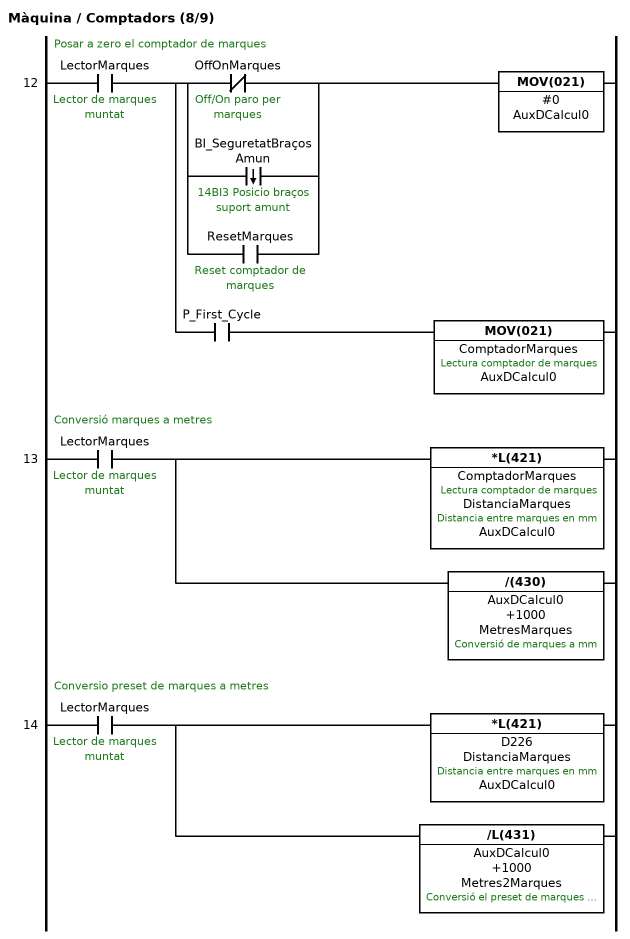
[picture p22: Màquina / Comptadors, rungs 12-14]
; rung 12: Posar a zero el comptador de marques
LD LectorMarques  ; Lector de marques muntat
OUT TR0
LDNOT OffOnMarques  ; Off/On paro per marques
%OR BI_SeguretatBraçosAmun  ; 14BI3 Posicio braços suport amunt
OR ResetMarques  ; Reset comptador de marques
ANDLD
MOV(021) #0 AuxDCalcul0
LD TR0
AND P_First_Cycle
MOV(021) ComptadorMarques AuxDCalcul0  ; Lectura comptador de marques
; rung 13: Conversió marques a metres
LD LectorMarques  ; Lector de marques muntat
*L(421) ComptadorMarques DistanciaMarques AuxDCalcul0  ; Lectura comptador de marques, Distancia entre marques en mm
/(430) AuxDCalcul0 +1000 MetresMarques  ; Conversió de marques a mm
; rung 14: Conversio preset de marques a metres
LD LectorMarques  ; Lector de marques muntat
*L(421) D226 DistanciaMarques AuxDCalcul0  ; Distancia entre marques en mm
/L(431) AuxDCalcul0 +1000 Metres2Marques  ; Conversió el preset de marques a metres

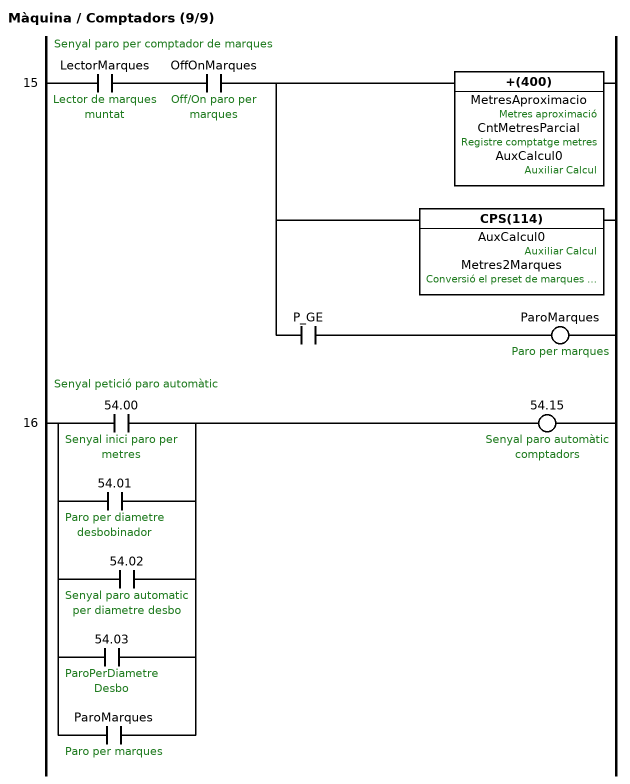
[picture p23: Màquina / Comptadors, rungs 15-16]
; rung 15: Senyal paro per comptador de marques
LD LectorMarques  ; Lector de marques muntat
AND OffOnMarques  ; Off/On paro per marques
+(400) MetresAproximacio CntMetresParcial AuxCalcul0  ; Metres aproximació, Registre comptatge metres, Auxiliar Calcul
CPS(114) AuxCalcul0 Metres2Marques  ; Auxiliar Calcul, Conversió el preset de marques a metres
AND P_GE
OUT ParoMarques  ; Paro per marques
; rung 16: Senyal petició paro automàtic
LD 54.00  ; Senyal inici paro per metres
OR 54.01  ; Paro per diametre desbobinador
OR 54.02  ; Senyal paro automatic per diametre desbo
OR 54.03  ; ParoPerDiametreDesbo
OR ParoMarques  ; Paro per marques
OUT 54.15  ; Senyal paro automàtic comptadors

### Section Arrosegament

; rung 0: Control pisor arrosegament
LD P_On
OUT TR0
AND H100.00  ; Forçar pisor arrosegament
@AND Estat_Preparacio  ; Maquina en estat de preparació
LD TR0
@AND SP_PisorArrosegament  ; 33SH1 Pulsador Off/On pisor arrosegament
OUT TR1
ANDNOT CtrlPisorArrosegament  ; Off/On pisor arrosegament
ORLD
LD TR1
AND CtrlPisorArrosegament  ; Off/On pisor arrosegament
KEEP(011) CtrlPisorArrosegament  ; Off/On pisor arrosegament
LD TR0
AND CtrlPisorArrosegament  ; Off/On pisor arrosegament
OUT PilotPisorArrosegament  ; 33SH1 Pilot pulsador pisor arrosegament
OUT PisorArrosegament  ; 33Y1 Pisor arrosegament

; rung 1: Control Off/On fre arrosegament
LD P_On
OUT TR0
@AND SP_FreArrosegament  ; 33SH2 Pulsador Off/On fre arrosegament
OUT TR1
ANDNOT CtrlFreArrosegament  ; Off/On Fre arrosegament
LD TR1
AND CtrlFreArrosegament  ; Off/On Fre arrosegament
KEEP(011) CtrlFreArrosegament  ; Off/On Fre arrosegament
LD TR0
LD Estat_Preparacio  ; Maquina en estat de preparació
OR Estat_Marxa  ; Màquina en producció
OR Estat_Paro  ; Màquina en procés de paro convencional
OR Estat_Enfilat  ; Màquina amb marxa d'enfilat
ANDLD
SET CtrlFreArrosegament  ; Off/On Fre arrosegament
LD TR0
LD CtrlFreArrosegament  ; Off/On Fre arrosegament
OR RunFwArrosegament  ; Senyal Run forward equip arrosegament
ANDLD
OUT PilotFreArrosegament  ; 33SH2 Pilot pulsador fre arrosegament
OUT FreArrosegament  ; 33Y2 Fre arrosegament
; rung 2: Reset equip arrosegament
LD SP_Reset  ; 06SH1 Pulsador reset
OUT 3220.09

; rung 3: Run equip arrosegament
LD Estat_Marxa  ; Màquina en producció
OR Estat_Preparacio  ; Maquina en estat de preparació
OR Estat_Paro  ; Màquina en procés de paro convencional
OR Estat_Enfilat  ; Màquina amb marxa d'enfilat
OUT RunRvArrosegament  ; Senyal Run reverse equip arrosegament
; rung 4: Consigna de velocitat equip arrosegament
LD P_On
CALL DB_VelocitatLineaHz : Escalat (In := Velocitat_SP, InMax := VelocitatMaxima, InMin := +0, OutMax := +5000, OutMin := +0, Out => 3221)  ; Consigna velocitat, Velocitat màxima, Referencia frequencia equip arrosegament en Hz
; rung 5: Velocitat actual de linea
LD P_On
CALL DB_VelocitatActual : Escalat (In := 3321, InMax := +5000, InMin := +0, OutMax := VelocitatMaxima, OutMin := +0, Out => VelocitatActual)  ; Feedback frequencia equip arrosegament, Velocitat màxima, Velocitat actual de màquina m/min
; rung 6: Comprova si hi ha hagut un cambi en la selecció del valor d'acceleració
LD P_On
CMP(020) Acceleracio_SP AuxAcceleracio_SP  ; Consigna d'acceleració, Auxiliar consigna acceleració
AND P_NE
MOV(021) Acceleracio_SP AuxAcceleracio_SP  ; Consigna d'acceleració, Auxiliar consigna acceleració

; rung 7: Envia el valor d'acceleració al equip
LD 200.02  ; Peticio actualitzacio acceleracio
AND P_0_02s
OR 200.00  ; AuxAccelBusy
CALL Acceleracio : _INVDRT401_WriteParameter (MasterUnitNo := &0, NodeNo := &2, INVtype := &1, ParameterNo := #200, Value := Acceleracio_SP, BUSY => 200.00, Done => 200.03)  ; Consigna d'acceleració, AuxAccelBusy, Actualitzacio acceleracio finalitzada
; rung 8: Control peticio actualització consigna acceleracio
@LD P_NE
OR P_First_Cycle
@OR SP_Reset  ; 06SH1 Pulsador reset
LD 200.03  ; Actualitzacio acceleracio finalitzada
KEEP(011) 200.02  ; Peticio actualitzacio acceleracio

; rung 9: Comprova si hi ha hagut un cambi en la selecció del valor de desacceleració
LD P_On
OUT TR0
AND Estat_Paro  ; Màquina en procés de paro convencional
@LD SP_ParoRapid  ; 08SP5 Pulsador paro ràpid
@OR ParoDetRetall  ; Paro per detectors retall
@OR ParoRapidDetRetall  ; Paro rapid per detectors retall
ANDLD
MOV(021) ParoRapid D1205  ; Temps desacceleració per paro ràpid, Selecció actual desacceleració
LD TR0
AND Estat_Stop  ; Màquina aturada sense alarmes
MOV(021) Desacceleracio_SP D1205  ; Consigna desacceleracio, Selecció actual desacceleració
LD TR0
AND AlarmaCritica  ; Alarma critica, aturada inmediata de màquina
MOV(021) #20 D1205  ; Selecció actual desacceleració
LD TR0
CMP(020) D1205 AuxDesacceleracio_SP  ; Selecció actual desacceleració, Auxiliar consigna desacceleracio
AND P_NE
MOV(021) D1205 AuxDesacceleracio_SP  ; Selecció actual desacceleració, Auxiliar consigna desacceleracio
; rung 10: Envia el valor de desacceleració al equip
LD 200.04  ; Peticio actualitzacio desacceleracio
AND P_0_02s
OR 200.01  ; AuxDesaccelBusy
CALL Desacceleracio : _INVDRT401_WriteParameter (MasterUnitNo := &0, NodeNo := &2, INVtype := &1, ParameterNo := #201, Value := AuxDesacceleracio_SP, BUSY => 200.01, Done => 200.05)  ; Auxiliar consigna desacceleracio, AuxDesaccelBusy, Actualitzacio desacceleracio finalitzada

; rung 11: Control peticio actualització consigna desacceleracio
@LD P_NE
OR P_First_Cycle
@OR SP_Reset  ; 06SH1 Pulsador reset
LD 200.05  ; Actualitzacio desacceleracio finalitzada
KEEP(011) 200.04  ; Peticio actualitzacio desacceleracio

### Section Rebobinador

; rung 0: Off/On Desbobinador
LD P_On
OUT TR0
LD SP_Marxa  ; 08SH3 Pulsador de marxa
LD Estat_Stop  ; Màquina aturada sense alarmes
OR Estat_Preparacio  ; Maquina en estat de preparació
ANDLD
LDNOT Estat_Preparacio  ; Maquina en estat de preparació
ANDNOT Estat_Marxa  ; Màquina en producció
ANDNOT Estat_Paro  ; Màquina en procés de paro convencional
ANDNOT 600.00
@AND 600.01  ; Aux pinces carro rebo menys
ORLD
ANDLD
LD TR0
@LD Estat_Stop  ; Màquina aturada sense alarmes
%ANDNOT Estat_Enfilat  ; Màquina amb marxa d'enfilat
LD 600.00
@AND 600.01  ; Aux pinces carro rebo menys
ORLD
ANDLD
KEEP(011) 600.00
LD TR0
ANDNOT Estat_emergència  ; Màquina en estat de paro d'emergència
OUT TR0
AND 600.00
OUT PincesCarroMes  ; 23Y2 Pinces carro a més
LD TR0
ANDNOT 600.00
OUT PincesCarroMenys  ; 23Y1 Pinces carro a menys
; rung 1: Reset equip Rebobinador
LD SP_Reset  ; 06SH1 Pulsador reset
OUT 3210.09
; rung 2: Control run i sentit rebobinador
LD Estat_Preparacio  ; Maquina en estat de preparació
OR Estat_Marxa  ; Màquina en producció
OR Estat_Paro  ; Màquina en procés de paro convencional
OR ActivarExpulsor  ; 13Y1 Expulsor Activat
OUT TR0
LDNOT ActivarExpulsor  ; 13Y1 Expulsor Activat
ANDNOT H110.00  ; Sentit bobinat
LD ActivarExpulsor  ; 13Y1 Expulsor Activat
AND H110.00  ; Sentit bobinat
ORLD
ANDLD
ANDNOT AlarmaCritica  ; Alarma critica, aturada inmediata de màquina
OUT 3210.00  ; Run Fw motor rebobinador
LD TR0
LDNOT ActivarExpulsor  ; 13Y1 Expulsor Activat
AND H110.00  ; Sentit bobinat
LD ActivarExpulsor  ; 13Y1 Expulsor Activat
ANDNOT H110.00  ; Sentit bobinat
ORLD
ANDLD
ANDNOT AlarmaCritica  ; Alarma critica, aturada inmediata de màquina
OUT 3210.01  ; Run Rv motor rebobinador

; rung 3: Control fre rebobinador
LD 3210.00  ; Run Fw motor rebobinador
OR 3210.01  ; Run Rv motor rebobinador
OR 111.00  ; Off/On freno rebobinador
OUT FreRebobinador  ; 14Y1 Fre rebobinador
; rung 4: Anula forçat manual de freno de rebobinador
LDNOT Estat_Stop  ; Màquina aturada sense alarmes
RSET 111.00  ; Off/On freno rebobinador

; rung 5: Càlcul velocitat de linea amb Hz de rebobinador
LDNOT ActivarExpulsor  ; 13Y1 Expulsor Activat
OUT TR0
+(400) VelocitatActual SobrevelocitatRebo AuxCalcul0  ; Velocitat actual de màquina m/min, Sobrevelocitat rebobinador en m/min, Auxiliar Calcul
*L(421) AuxCalcul0 +1856 AuxCalcul0  ; Auxiliar Calcul
MOV(021) 3360 AuxDCalcul0  ; Diametre rebobinador
MOV(021) +0 W11
/L(431) AuxCalcul0 AuxDCalcul0 AuxCalcul0  ; Auxiliar Calcul
MOV(021) AuxCalcul0 VelocitatLineaRebo  ; Auxiliar Calcul, Velocitat en Hz de motor rebo
CPS(114) +0 VelocitatLineaRebo  ; Velocitat en Hz de motor rebo
AND P_LT
MOV(021) VelocitatLineaRebo 3213  ; Velocitat en Hz de motor rebo
LD TR0
LD P_GE
LD Estat_Paro  ; Màquina en procés de paro convencional
AND Velocitat0Arrosegament  ; Velocitat 0 equip arrosegament
ORLD
ANDLD
MOV(021) +0 3213
; rung 6: Velocitat d'expulsio de bobines
LD ActivarExpulsor  ; 13Y1 Expulsor Activat
MOV(021) VelocitatExpulsioBobines 3213  ; Velocitat del Rebobinador al expulsar bobina

; rung 7: Fricció Eix 1, calculem amb un altre escalat, ja que la sortida està a la analògica AM del variador carro
LD P_On
CALL FriccioEix1 : FriccioEix1 (Tir := TirRebo1_SP, Decreixent := TaperRebo1, Ample := D1113, DiametreActual := 3360, DiametreMaxim := DiametreMaximRebo, DiametreMinim := DiametreMinimRebo, PressioMax := PresioMaximaFriccio, MinOut := D1131, Pressio => D1100)  ; Consigna de tir rebobinador 1, Taper tir rebobinador 1, Ample bobina rebo 1, Diametre rebobinador, Diametre màxim rebobinador, Diametre mínim de rebobinador, Pressió màxima, Sortida pressio mínima, Fricció eix 1
; rung 8: Pressió eix rebobinador 2, calculem amb un escalat diferent, ja que la sortida és l'analog FM del variador Rw A1000
LD P_On
CALL FriccioRebo2 : FriccioEix2 (Tir := TirRebo2_SP, Decreixent := TaperRebo2, Ample := D1123, DiametreActual := 3360, DiametreMaxim := DiametreMaximRebo, DiametreMinim := DiametreMinimRebo, PressioMax := PresioMaximaFriccio, MinOut := D1131, Pressio => D1101)  ; Consigna de tir rebobinador 2, Taper tir rebobinador 2, Ample bobina rebo 2, Diametre rebobinador, Diametre màxim rebobinador, Diametre mínim de rebobinador, Pressió màxima, Sortida pressio mínima, Fricció eix 2
; rung 9: Donar pressió 0 quan demanda de tir igual a 0
LD P_On
OUT TR0
AND=S(302) TirRebo1_SP #0  ; Consigna de tir rebobinador 1
MOV(021) #0 D1100  ; Fricció eix 1
LD TR0
AND=S(302) TirRebo2_SP #0  ; Consigna de tir rebobinador 2
MOV(021) #0 D1101  ; Fricció eix 2

; rung 10: Carrega presio màxima a eixos mentre expulsors activats, canviem els 1400 per els 16384, només a eix2 (D1101)
LD ActivarExpulsor  ; 13Y1 Expulsor Activat
AND Expulsors_Muntats  ; Expulsors instal.lats a màquina
MOV(021) +16384 D1101  ; Fricció eix 2
MOV(021) +1400 D1100  ; Fricció eix 1
; rung 11: Movem la sortida de friccio calculada directe a la paraula 3212 del variador, sortida analògica FM del nou variador A1000 Yaskawa.
LD P_On
MOV(021) D1101 3212  ; Fricció eix 2

### Section Tall

; rung 0: Control extractor de retall
LD ExtractorRetall_Muntat  ; Extractor de retall muntat a la màquina
OUT TR0
@AND SP_ExtractorRetall  ; 17SH1 Pulsador Off/On extractor de retall
OUT TR1
ANDNOT OffOnExtractorRetall  ; Off/On extractor de retall
LD TR1
AND OffOnExtractorRetall  ; Off/On extractor de retall
LD TR0
AND TèrmicExtractorRetall  ; 17F1 Tèrmic extractor de retall
ORLD
KEEP(011) OffOnExtractorRetall  ; Off/On extractor de retall
LD TR0
AND OffOnExtractorRetall  ; Off/On extractor de retall
LD TimArrancExtractorRetall  ; Temporització per a l'arranc del extractor de retall
LDNOT TimArrancExtractorRetall  ; Temporització per a l'arranc del extractor de retall
AND P_1s
ORLD
ANDLD
OUT PilotExtractor  ; 17SH1 Pilot pulsador extractor de retall
; rung 1: Control arranc extractor de retall
LD ExtractorRetall_Muntat  ; Extractor de retall muntat a la màquina
ANDNOT TèrmicExtractorRetall  ; 17F1 Tèrmic extractor de retall
LD OffOnExtractorRetall  ; Off/On extractor de retall
LD Estat_Marxa  ; Màquina en producció
OR Estat_Paro  ; Màquina en procés de paro convencional
AND ForçarExtractorRetall  ; Forçar extractor de retall
ORLD
ANDLD
OUT TR0
TIM 0150 #50  ; Temporització per a l'arranc del extractor de retall
ANDNOT TimArrancExtractorRetall  ; Temporització per a l'arranc del extractor de retall
OUT ArrancExtractorRetall  ; 17K2 Arranc extractor de retall
LD TR0
OUT ExtractorRetall  ; 17K1 Extractor retall
; rung 2: Control oscil.lació ganivetas
LD OscilacioGanivetas_Muntat  ; Oscilacio Ganivetas muntat a la màquina
AND SL_OscilacioGanivetas  ; 18SL1 Selector oscil.lacio ganivetas
OUT OscilacioGanivetas  ; 18K1 Contactor motor oscil.lacio ganivetas

; rung 3: Comprovar si els tots els detectors estan a On
LD DetectorsRetall_Muntat  ; Detectors extractor de retall muntats a la màquina
LD DetectorRetall1  ; 17BF1 Detector extractor de retall 1
ORNOT H150.00  ; OffOnDetectorRetall1
LD DetectorRetall2  ; 17BF2 Detector extractor de retall 2
ORNOT H150.01  ; OffOnDetectorRetall2
ANDLD
OR>=(325) D1601 VelocitatActual  ; Velocitat minima deteccio retall, Velocitat actual de màquina m/min
LDNOT H150.00  ; OffOnDetectorRetall1
ANDNOT H150.01  ; OffOnDetectorRetall2
ORLD
ANDLD
OUT EstatDetectorsRetall  ; Detectors retall Ok
; rung 4: Generació de avis o paro per detectors de retall 0=Avis 1=Paro 2=Paro ràpid
LD DetectorsRetall_Muntat  ; Detectors extractor de retall muntats a la màquina
ANDNOT EstatDetectorsRetall  ; Detectors retall Ok
OUT TR0
AND=(300) D1602 #2  ; Mode avis/paro detectors retall
OUT ParoDetRetall  ; Paro per detectors retall
LD TR0
AND=(300) D1602 #3  ; Mode avis/paro detectors retall
OUT ParoRapidDetRetall  ; Paro rapid per detectors retall
; rung 5: Control laser posicionament mandrins
LD LaserMandrins_Muntat  ; Laser posicionat mandrins muntats a la màquina
AND OffOnLaserMandrins  ; Off/On Laser posicionat mandrins
OUT TR0
TIM 0151 TempsLaserMandrinsOn  ; Temps On Laser posicionat mandrins, Temporització On laser mandrins
AND TimLaserMandrins  ; Temporització On laser mandrins
RSET OffOnLaserMandrins  ; Off/On Laser posicionat mandrins
LD TR0
OUT LaserMandrins  ; 15K1 Laser posicionador mandrins
; rung 6: Control barres antiestàtiques
LD BarresAntiestatica_Muntat  ; Barres antiestàtiques muntades a màquina
AND OffOnBarresAntiestàtiques  ; Off/On barres antiestàtiques
OUT BarresAntiestatica  ; 16K1 Barres antiestàtiques

### Section Carro

; rung 0: Reset equip carro
LD SP_Reset  ; 06SH1 Pulsador reset
OUT ResetCarro  ; Reset equip carro
; rung 1: Activar/Desactivar pistons tancament braços rebo
LD P_On
AND Tanques_Rebo_Muntats  ; Tanques pneumatiques a màquina
OUT TR0
@LD SL_BraçAbaix  ; Selector braços suport eixos rebobinador abaix
ORNOT BI_SeguretatBraçosAmun  ; 14BI3 Posicio braços suport amunt
ANDLD
LD TR0
@AND BI_SeguretatBraçosAmun  ; 14BI3 Posicio braços suport amunt
KEEP(011) OnOffTanquesBraços  ; 14K2 Obrir/tancar pistons pneumatics braços

; rung 2: Selecció pujar braços suport
LD P_On
LD ExpulsorHome  ; 13B2 Reed Expulsor Home
ORNOT Expulsors_Muntats  ; Expulsors instal.lats a màquina
ANDLD
OUT TR0
ANDNOT CarroManualFw  ; Moviment carro endevant manual
ANDNOT CarroManualRv  ; Moviment carro endarrera manual
@AND SL_BraçAmun  ; Selector braços suport eixos rebobinador amunt
LDNOT OnOffTanquesBraços  ; 14K2 Obrir/tancar pistons pneumatics braços
OR Tanques_Rebo_Muntats  ; Tanques pneumatiques a màquina
ANDLD
LD TR0
LDNOT SeguretatBraçAmun  ; 14SF1 Final de cursa seguretat posició braços suport rebobinador amun
OR BI_SeguretatBraçosAmun  ; 14BI3 Posicio braços suport amunt
OR SP_Paro  ; 08SH1 Pulsador paro
@OR SL_BraçAbaix  ; Selector braços suport eixos rebobinador abaix
ORNOT SeguretatTancamentRebo1  ; 14BI1 Inductiu seguretat tancament rebobinador 1
ORNOT SeguretatTancamentRebo2  ; 14BI2 Inductiu seguretat tancament eix rebobinador 2
ANDLD
KEEP(011) 410.00  ; Pujar motor braços suport

; rung 3: Selecció baixar braços suport
LD P_On
OUT TR0
ANDNOT CarroManualFw  ; Moviment carro endevant manual
ANDNOT CarroManualRv  ; Moviment carro endarrera manual
AND SL_BraçAbaix  ; Selector braços suport eixos rebobinador abaix
LDNOT OnOffTanquesBraços  ; 14K2 Obrir/tancar pistons pneumatics braços
OR Tanques_Rebo_Muntats  ; Tanques pneumatiques a màquina
ANDLD
LD TR0
LDNOT SeguretatBraçAbaix  ; 14SF2 Final de cursa seguretat posició braços suport rebobinador abaix
OR SP_Paro  ; 08SH1 Pulsador paro
@OR SL_BraçAmun  ; Selector braços suport eixos rebobinador amunt
ORNOT SeguretatTancamentRebo1  ; 14BI1 Inductiu seguretat tancament rebobinador 1
ORNOT SeguretatTancamentRebo2  ; 14BI2 Inductiu seguretat tancament eix rebobinador 2
ANDLD
KEEP(011) 410.01  ; Baixar motor braços suport eixos
; rung 4: Sequencia moviment carro manual 401.0 Stop Rv, 401.2 Fw, 401.2 Stop Fw, 401.3 Rv
LD Estat_Alarma  ; Màquina en estat d'alarma
OR Estat_Stop  ; Màquina aturada sense alarmes
OUT TR0
@AND SP_Carro  ; 23SP1 Pulsador carro
ASL(025) 401  ; Sequencia carro
LD TR0
AND 401.04
LD Estat_emergència  ; Màquina en estat de paro d'emergència
OR P_First_Cycle
ORLD
MOV(021) &1 401  ; Sequencia carro

; rung 5: Comprova quin dels dos carros te el valor més petit
LD P_On
AND<=S(317) D1405 D1415  ; Error posició pisor 1, Error posicio pisor 2
OUT 403.00
; rung 6: Comprova si hi ha algun valor negatiu de pisor
LD P_On
LD<=S(317) D1405 &0  ; Error posició pisor 1
OR<=S(317) D1415 &0  ; Error posicio pisor 2
ANDLD
OUT 403.01
; rung 7: Tope darrera carro
LD P_On
CPS(114) D1490 3360  ; Tope carro enrera, Diametre rebobinador
AND P_LT
OUT 403.07  ; Tope carro darrera
; rung 8: Stop carro endevant en manual quan pisor  =0 o negatiu
LD CarroManualFw  ; Moviment carro endevant manual
AND 403.01
MOV(021) &4 401  ; Sequencia carro
; rung 9: Stop carro endarrera en manual quan encoder >= Tope carro enrrera
LD CarroManualRv  ; Moviment carro endarrera manual
AND 403.07  ; Tope carro darrera
MOV(021) &1 401  ; Sequencia carro
; rung 10: Velocitat braços rebobinador
LD MotorBraçosSuport  ; 24K2 Contactor selecció motor braços suport
MOV(021) Velocitat_braços 3231  ; Velocitat braços, Referencia velocitat equip carro

; rung 11: Selecció sentit de gir motor carro
LD P_On
OUT TR0
AND CarroManualFw  ; Moviment carro endevant manual
LD TR0
LD Estat_Marxa  ; Màquina en producció
OR Estat_Paro  ; Màquina en procés de paro convencional
OR Estat_Preparacio  ; Maquina en estat de preparació
ANDLD
OUT TR1
ANDNOT 403.01
ORLD
OUT 403.02  ; Auxiliar carro fw
LD TR1
AND 403.01
LD TR0
AND CarroManualRv  ; Moviment carro endarrera manual
ORLD
ANDNOT 403.07  ; Tope carro darrera
OUT 403.03  ; Auxiliar carro Rv
; rung 12: Selecció consigna velocitat carro manual
LD CarroManualRv  ; Moviment carro endarrera manual
MOV(021) Velocitat_carro 3231  ; Velocitat del carro, Referencia velocitat equip carro
; rung 13: Selecció velocitat automàtica segons prioritat
LD Estat_Marxa  ; Màquina en producció
OR Estat_Preparacio  ; Maquina en estat de preparació
OR Estat_Paro  ; Màquina en procés de paro convencional
OR CarroManualFw  ; Moviment carro endevant manual
OUT TR0
ANDNOT 403.00
ANDNOT 403.01
MOV(021) D1415 3231  ; Error posicio pisor 2, Referencia velocitat equip carro
LD TR0
ANDNOT 403.00
AND 403.01
NEG(160) D1415 3231  ; Error posicio pisor 2, Referencia velocitat equip carro
LD TR0
AND 403.00
ANDNOT 403.01
MOV(021) D1405 3231  ; Error posició pisor 1, Referencia velocitat equip carro
LD TR0
AND 403.00
AND 403.01
NEG(160) D1405 3231  ; Error posició pisor 1, Referencia velocitat equip carro

; rung 14: Activació control motor carro
LDNOT 410.00  ; Pujar motor braços suport
ANDNOT 410.01  ; Baixar motor braços suport eixos
OUT 403.04  ; AuxMotorCarro
; rung 15: Selecció control motor braços suport
LDNOT MotorCarro  ; 24K1 Contactor selecció motor carro
OUT 403.05  ; AuxMotorBrasos
; rung 16: Senyal de retard per a la conexió del contactor de motor
LD P_On
OUT TR0
%LD 403.04  ; AuxMotorCarro
%OR 403.05  ; AuxMotorBrasos
ANDLD
SET 403.06  ; Retard Conexio Contactor
LD TR0
AND 403.06  ; Retard Conexio Contactor
TIM 0400 #5  ; Temporitzador retard a la conexió dels contactors de selecció de motor
LD TR0
AND T0400  ; Temporitzador retard a la conexió dels contactors de selecció de motor
RSET 403.06  ; Retard Conexio Contactor
; rung 17: Activació contactor selecció de motor
LD P_On
ANDNOT 403.06  ; Retard Conexio Contactor
OUT TR0
AND 403.04  ; AuxMotorCarro
OUT MotorCarro  ; 24K1 Contactor selecció motor carro
LD TR0
AND 403.05  ; AuxMotorBrasos
OUT MotorBraçosSuport  ; 24K2 Contactor selecció motor braços suport

; rung 18: Consigna sentit de gir equip carro
LD P_On
OUT TR0
LD MotorCarro  ; 24K1 Contactor selecció motor carro
AND 403.02  ; Auxiliar carro fw
LD MotorBraçosSuport  ; 24K2 Contactor selecció motor braços suport
AND 410.00  ; Pujar motor braços suport
LD ExpulsorHome  ; 13B2 Reed Expulsor Home
ORNOT Expulsors_Muntats  ; Expulsors instal.lats a màquina
ANDLD
ORLD
ANDLD
OUT RunFwCarro  ; Run Carro Fw
LD TR0
LD MotorCarro  ; 24K1 Contactor selecció motor carro
AND 403.03  ; Auxiliar carro Rv
LD MotorBraçosSuport  ; 24K2 Contactor selecció motor braços suport
AND 410.01  ; Baixar motor braços suport eixos
ORLD
ANDLD
OUT RunRvCarro  ; Run Carro Rv
; rung 19: Si estat d'emergencia posa a 0 la pressio de pisor i activa vàlvula retoces pisor
LD P_On
OUT TR0
AND Estat_emergència  ; Màquina en estat de paro d'emergència
MOV(021) +0 AuxCalcul0  ; Auxiliar Calcul
LD TR0
ANDNOT Estat_emergència  ; Màquina en estat de paro d'emergència
MOV(021) D1400 AuxCalcul0  ; Pressio pisor eix 1, Auxiliar Calcul
LD TR0
ANDNOT Estat_emergència  ; Màquina en estat de paro d'emergència
OUT PresorRebobinador  ; 14Y2 Presor rebobinador
; rung 20: Comprova si hi ha hagut un cambi en la selecció del valor de pressió pisor 1
LD P_On
CMP(020) AuxCalcul0 D1401  ; Auxiliar Calcul, Auxiliar presió pisor 1
AND P_NE
MOV(021) AuxCalcul0 D1401  ; Auxiliar Calcul, Auxiliar presió pisor 1

; rung 21: Envia el valor de pressió de pisor 1 al equip
LD 400.05  ; Peticio actualitzacio pressio pisor 1
AND P_0_02s
OR 400.00  ; Senyal Pressio pisor 1 busy
CALL PressioPisor1 : _INVDRT401_WriteParameter (MasterUnitNo := &0, NodeNo := &2, INVtype := &1, ParameterNo := #7, Value := D1401, BUSY => 400.00, Done => 400.04)  ; Auxiliar presió pisor 1, Senyal Pressio pisor 1 busy, Finalitzada actualitzacio de presio de pisor 1
; rung 22: Control peticio actualització consigna pressio pisor 1
@LD P_NE
OR P_First_Cycle
@OR SP_Reset  ; 06SH1 Pulsador reset
LD 400.04  ; Finalitzada actualitzacio de presio de pisor 1
KEEP(011) 400.05  ; Peticio actualitzacio pressio pisor 1
; rung 23: Si estat d'emergencia posa a 0 la pressio de pisor
LD P_On
OUT TR0
AND Estat_emergència  ; Màquina en estat de paro d'emergència
MOV(021) +0 AuxCalcul0  ; Auxiliar Calcul
LD TR0
ANDNOT Estat_emergència  ; Màquina en estat de paro d'emergència
MOV(021) D1410 AuxCalcul0  ; Pressio pisor 2, Auxiliar Calcul
; rung 24: Comprova si hi ha agut algun cambi en la consigna de pressio del pisor 2
LD P_On
CMP(020) AuxCalcul0 D1411  ; Auxiliar Calcul
AND P_NE
MOV(021) AuxCalcul0 D1411  ; Auxiliar Calcul

; rung 25: Envia el valor de pressió de pisor 2 al equip
LD 400.07  ; Peticio actualitzacio pressio pisor 2
AND P_0_02s
OR 400.01
CALL PressioPisor2 : _INVDRT401_WriteParameter (MasterUnitNo := &0, NodeNo := &2, INVtype := &1, ParameterNo := #8, Value := D1411, BUSY => 400.01, Done => 400.06)  ; Finalitzacio actualitzacio pressio pisor 2
; rung 26: Control peticio actualització consigna acceleracio
@LD P_NE
OR P_First_Cycle
@OR SP_Reset  ; 06SH1 Pulsador reset
LD 400.06  ; Finalitzacio actualitzacio pressio pisor 2
KEEP(011) 400.07  ; Peticio actualitzacio pressio pisor 2
; rung 27: Carrega valor de posició de pisor eix rebobinador 1
LD P_0_02s
OR 400.02
CALL PosicioPisor1 : _INVDRT201_ReadParameter (MasterUnitNo := &0, NodeNo := &3, ParameterNo := &117, BUSY => 400.02, Value => D1402)  ; Posició pisor eix 1
; rung 28: Càlcul error de posició pisor rebobinador 1 -50% / 50%
LD P_On
CALL DB_ErrorPosicioPisor1 : Escalat (In := D1402, InMax := D1403, InMin := D1404, OutMax := +2000, OutMin := -2000, Out => D1405)  ; Posició pisor eix 1, Posició pisor eix 2, Error posició pisor 1
; rung 29: Carrega valor de posició de pisor eix rebobinador 2
LD P_0_02s
OR 400.03
CALL PosicioPisor2 : _INVDRT201_ReadParameter (MasterUnitNo := &0, NodeNo := &3, ParameterNo := &121, BUSY => 400.03, Value => D1412)  ; Posicio pisor rebo 2

; rung 30: Càlcul error de posició pisor rebobinador 2 -50% / 50%
LD P_On
CALL DB_ErrorPosicioPisor2 : Escalat (In := D1412, InMax := D1413, InMin := D1414, OutMax := +2000, OutMin := -2000, Out => D1415)  ; Posicio pisor rebo 2, Error posicio pisor 2
; rung 31: Envia el valor de preset al encoder del carro
@LD 420.00  ; Generar preset de posició encoder
ESATR(722) D1420 D1427  ; Tope carro endarrera
; rung 32: Fa un set/save dels paràmetres enviats a l'encoder
%LD 420.00  ; Generar preset de posició encoder
EXPLT(720) D1430 D1440 D1436
; rung 33: Escribim el valor de la paraula D1100 a la sortida analògica AM del variador del carro.
LD P_On
OR 301.02
CALL Friccio_1_Prova : _INVDRT401_WriteParameter (MasterUnitNo := &0, NodeNo := &3, INVtype := &0, ParameterNo := #7, Value := D1100, BUSY => 301.02)  ; Fricció eix 1

### Section AlineadorRe

; rung 0: Control Off/On alineador
LD P_On
OUT TR0
@AND SP_Alineador  ; 44SH1 Pulsador mode alineador
OUT TR1
ANDNOT 500.00  ; Mode alineador
LD TR1
AND 500.00  ; Mode alineador
KEEP(011) 500.00  ; Mode alineador
LD TR0
AND 500.00  ; Mode alineador
OUT PilotAlineador  ; 44SH1 Pilot pulsador alineador
LD TR0
AND SP_ObrirDesbo  ; 55SP1 Pulsador obrir desbobinador
RSET 500.00  ; Mode alineador
; rung 1: Control inici alineador en mode velocitat amb histeresi de 1m/min
LD 500.00  ; Mode alineador
OUT TR0
CMP(020) VelocitatActual D1505  ; Velocitat actual de màquina m/min, Velocitat inici alineador
AND P_GE
SET 500.06  ; Ctrl mode velocitat alineador
LD TR0
-(410) D1505 +1 AuxCalcul0  ; Velocitat inici alineador, Auxiliar Calcul
CPS(114) VelocitatActual AuxCalcul0  ; Velocitat actual de màquina m/min, Auxiliar Calcul
AND P_LT
RSET 500.06  ; Ctrl mode velocitat alineador
; rung 2: Reset equip
LD SP_Reset  ; 06SH1 Pulsador reset
OUT ResetAlineador  ; Reset equip alineador

; rung 3: Lectura valor capçal alineador Re
LD 500.00  ; Mode alineador
LD P_0_1s
OR 501.00
ANDLD
CALL DB_CapsalAlineador : _INVDRT201_ReadParameter (MasterUnitNo := &0, NodeNo := &4, ParameterNo := &117, BUSY => 501.00, Done => 501.01, Value => D1500)  ; Tensió capçar alineador
; rung 4: Cada vegada que finalitzi la lectura dona consigna de iniciar una nova lectura
LDNOT 501.00
OUT 501.02  ; Peticio actualitzacio guany P alineador
; rung 5: Estableix limits de velocitat de correccio alineador
LD 500.00  ; Mode alineador
-(410) D1500 +250 D1501  ; Tensió capçar alineador, ErrorAlineador
; rung 6: Retarda la entrada del Run respecte la senyal de activació del PID
LD 500.00  ; Mode alineador
OUT TR0
TIM 0500 #5  ; Retard a la conexió del Run alineador respecte el PID
AND T0500  ; Retard a la conexió del Run alineador respecte el PID
DIFU(013) 500.04  ; Flanc inici alineador mode automàtic
LD TR0
AND 500.04  ; Flanc inici alineador mode automàtic
LDNOT 500.00  ; Mode alineador
KEEP(011) 500.05  ; Ok inici run alineador mode automàtic

; rung 7: Seleccio de sentit de correcció segons el valor del capçal Re
LD 500.00  ; Mode alineador
LD>=S(327) D1501 +0  ; ErrorAlineador
LD H120.00  ; Sentit Alineador
ANDNOT BI_SeguretatHusillo  ; 54BI6 Detector desbo EASY seguretat husillo
ANDNOT BI_TopeDesfasaeDreta  ; 54BI5 Detector tope desfasar dreta desbobinador EASY
ANDNOT BI_TopeCostatCilindre  ; 54BI7 Detector tope costat cilindre desbo EASY
LDNOT H120.00  ; Sentit Alineador
ANDNOT BI_TopeCostatHusillo  ; 54BI2 Detector desbo EASY tope costat husillo
ANDNOT BI_TopeDesfasarEsquerra  ; 54BI3 Detector desbo EASY tope desfasar esquerra
ANDNOT SeguretatTencarDesbo  ; 54BI1 Reed seguretat cilindre tancament desbobinador
ORLD
ANDLD
LD<=S(317) D1501 +0  ; ErrorAlineador
LD H120.00  ; Sentit Alineador
ANDNOT BI_TopeCostatHusillo  ; 54BI2 Detector desbo EASY tope costat husillo
ANDNOT BI_TopeDesfasarEsquerra  ; 54BI3 Detector desbo EASY tope desfasar esquerra
ANDNOT SeguretatTencarDesbo  ; 54BI1 Reed seguretat cilindre tancament desbobinador
LDNOT H120.00  ; Sentit Alineador
ANDNOT BI_SeguretatHusillo  ; 54BI6 Detector desbo EASY seguretat husillo
ANDNOT BI_TopeDesfasaeDreta  ; 54BI5 Detector tope desfasar dreta desbobinador EASY
ANDNOT BI_TopeCostatCilindre  ; 54BI7 Detector tope costat cilindre desbo EASY
ORLD
ANDLD
ORLD
ANDLD
AND 500.05  ; Ok inici run alineador mode automàtic
AND 500.06  ; Ctrl mode velocitat alineador
OUT 500.01  ; AuxAlineadorFw
; rung 8: Off/On PID alineador en mode automàtic
LDNOT 500.00  ; Mode alineador
OUT 3240.03
; rung 9: Freno del motor alineador
LD RunRvAlineador  ; Run Rv motor alineador
OR RunFwAlineador  ; Run Fw motor alineador
OUT 12.15

### Section Desbobinador

; rung 0: Off/On Desbobinador
LD P_On
OUT TR0
@AND Estat_Preparacio  ; Maquina en estat de preparació
ANDNOT OffOnDesbo  ; Biestable Off/On desbobinador
LD TR0
AND EstatMaquinaParadaOk  ; Condicions de màquina aturada
@AND SP_Desbobinador  ; SP Pulsador Off/On desbobinador
OUT TR1
ANDNOT OffOnDesbo  ; Biestable Off/On desbobinador
ORLD
LD TR1
AND OffOnDesbo  ; Biestable Off/On desbobinador
KEEP(011) OffOnDesbo  ; Biestable Off/On desbobinador
LD TR0
AND OffOnDesbo  ; Biestable Off/On desbobinador
OUT PilotDesbobinador  ; 53SH1 Pilot pulsador desbobinador
; rung 1: Retard obertura desbobinador
LD EstatMaquinaParadaOk  ; Condicions de màquina aturada
LDNOT SeguretatPosicioDesbo  ; 58SF1 Final de cursa seguretat posició Desbobinador
ORNOT PickUp_Muntat  ; PickUp instal.lat a la màquina
ANDLD
AND SP_ObrirDesbo  ; 55SP1 Pulsador obrir desbobinador
TIM 0300 #30  ; Retard obertura desbo
ANDNOT T0300  ; Retard obertura desbo
AND P_1s
OUT 302.00  ; Auxiliar senyal desbobinador
; rung 2: Moure husillo a l'esquerra per obrir desbo EASY
LD T0300  ; Retard obertura desbo
AND BI_TopeCostatCilindre  ; 54BI7 Detector tope costat cilindre desbo EASY
ANDNOT BI_TopeCostatHusillo  ; 54BI2 Detector desbo EASY tope costat husillo
OUT AuxHusilloEsquerra  ; Maniobra obrir tencar i desfasar desbo EASY
; rung 3: Moure husillo a la dreta per tencar desbo EASY
LD SP_TencarDesbo  ; 55SP2 Pulsador tencar desbobinador
ANDNOT BI_Centrat  ; 54BI4 Detector posició central alineador desbo EASY
ANDNOT BI_TopeDesfasaeDreta  ; 54BI5 Detector tope desfasar dreta desbobinador EASY
ANDNOT BI_SeguretatHusillo  ; 54BI6 Detector desbo EASY seguretat husillo
OUT AuxHusilloDreta  ; Maniobra obrir tencar i desfasar desbo EASY

; rung 4: Control obrir cilindre tencament desbobinador EASY
LD T0300  ; Retard obertura desbo
ANDNOT SP_TencarDesbo  ; 55SP2 Pulsador tencar desbobinador
ANDNOT BI_TopeCostatCilindre  ; 54BI7 Detector tope costat cilindre desbo EASY
ANDNOT Estat_emergència  ; Màquina en estat de paro d'emergència
OUT ObrirDesboEASY  ; 54Y2 Obrir desbobinador EASY
; rung 5: Control tencar cilindre tencament desbobinador EASY
LD BI_Centrat  ; 54BI4 Detector posició central alineador desbo EASY
OR BI_TopeDesfasaeDreta  ; 54BI5 Detector tope desfasar dreta desbobinador EASY
AND SP_TencarDesbo  ; 55SP2 Pulsador tencar desbobinador
OR 52.03  ; Màquina en moviment
OR SP_DesfasarDreta  ; 44SP5 Pulsador desfasar dreta
OR SP_DesfasarEsquerra  ; 44SP3 Pulsador desfasar esquerra
ANDNOT SP_ObrirDesbo  ; 55SP1 Pulsador obrir desbobinador
ANDNOT Estat_emergència  ; Màquina en estat de paro d'emergència
OUT TencarDesboEASY  ; 54Y1 Tencar desbobinador EASY
; rung 6: Control moviment husillo cap a l'esquerra
LDNOT 500.00  ; Mode alineador
LDNOT SP_ObrirDesbo  ; 55SP1 Pulsador obrir desbobinador
ANDNOT SP_TencarDesbo  ; 55SP2 Pulsador tencar desbobinador
AND SP_DesfasarEsquerra  ; 44SP3 Pulsador desfasar esquerra
ANDNOT SeguretatTencarDesbo  ; 54BI1 Reed seguretat cilindre tancament desbobinador
ANDNOT BI_TopeDesfasarEsquerra  ; 54BI3 Detector desbo EASY tope desfasar esquerra
OR AuxHusilloEsquerra  ; Maniobra obrir tencar i desfasar desbo EASY
ANDLD
ANDNOT BI_TopeCostatHusillo  ; 54BI2 Detector desbo EASY tope costat husillo
ANDNOT SeguretatTencarDesbo  ; 54BI1 Reed seguretat cilindre tancament desbobinador
ANDNOT Estat_emergència  ; Màquina en estat de paro d'emergència
OUT 304.00  ; Aux Run Fw alineador manual
; rung 7: Control moviment husillo cap a la dreta
LDNOT 500.00  ; Mode alineador
ANDNOT SP_ObrirDesbo  ; 55SP1 Pulsador obrir desbobinador
ANDNOT SP_TencarDesbo  ; 55SP2 Pulsador tencar desbobinador
AND SP_DesfasarDreta  ; 44SP5 Pulsador desfasar dreta
ANDNOT BI_TopeDesfasaeDreta  ; 54BI5 Detector tope desfasar dreta desbobinador EASY
ANDNOT BI_TopeCostatCilindre  ; 54BI7 Detector tope costat cilindre desbo EASY
OR AuxHusilloDreta  ; Maniobra obrir tencar i desfasar desbo EASY
ANDNOT BI_SeguretatHusillo  ; 54BI6 Detector desbo EASY seguretat husillo
ANDNOT Estat_emergència  ; Màquina en estat de paro d'emergència
OUT 304.01  ; Aux Run Rv alineador manual

; rung 8: Consigna velocitat manual alineador
LDNOT 500.00  ; Mode alineador
OUT TR0
AND 304.00  ; Aux Run Fw alineador manual
MOV(021) +0 3241  ; Referencia velocitat alineador
LD TR0
AND 304.01  ; Aux Run Rv alineador manual
MOV(021) +5000 3241  ; Referencia velocitat alineador
LD TR0
ANDNOT 304.00  ; Aux Run Fw alineador manual
ANDNOT 304.01  ; Aux Run Rv alineador manual
MOV(021) +2500 3241  ; Referencia velocitat alineador
; rung 9: Consigna velocitat alineador automàtic
LD 500.00  ; Mode alineador
MOV(021) +1500 3241  ; Referencia velocitat alineador
; rung 10: Control Run equip alineador
LD 304.00  ; Aux Run Fw alineador manual
OR 304.01  ; Aux Run Rv alineador manual
LD H120.00  ; Sentit Alineador
AND 500.00  ; Mode alineador
AND 500.01  ; AuxAlineadorFw
ORLD
ANDNOT Estat_emergència  ; Màquina en estat de paro d'emergència
OUT RunRvAlineador  ; Run Rv motor alineador
; rung 11: Control alineador (contrast invertit)
LDNOT H120.00  ; Sentit Alineador
AND 500.00  ; Mode alineador
AND 500.01  ; AuxAlineadorFw
ANDNOT Estat_emergència  ; Màquina en estat de paro d'emergència
OUT RunFwAlineador  ; Run Fw motor alineador
; rung 12: Control retard de la desconexió de la central hidraulica de 5s
LDNOT SP_PujarDesbo  ; 57SP2 Pulsador pujar desbobinador
ANDNOT SP_BaixarDesbo  ; 57SP1 Pulsador baixar desbobinador
ANDNOT DemHidraHandling  ; Demanda central hidraulica handlind
TIM 0301 #50  ; Retard a la desconexió de la central hidraulica

; rung 13: Control Off/On central hidràulica
LD SP_PujarDesbo  ; 57SP2 Pulsador pujar desbobinador
OR SP_BaixarDesbo  ; 57SP1 Pulsador baixar desbobinador
AND SP_SeguretatDesbo  ; 57SP3 Pulsador seguretat maniobra hidràulica
OR DemHidraHandling  ; Demanda central hidraulica handlind
ANDNOT T0301  ; Retard a la desconexió de la central hidraulica
ANDNOT Estat_emergència  ; Màquina en estat de paro d'emergència
ANDNOT 52.03  ; Màquina en moviment
ANDNOT TèrmicCentralHidràulica  ; 57F1 Tèrmic central hidràulica
OUT CentralHidraulica  ; 57K1 Central hidràulica
; rung 14: Control pujar desbobinador
LD SP_PujarDesbo  ; 57SP2 Pulsador pujar desbobinador
AND SP_SeguretatDesbo  ; 57SP3 Pulsador seguretat maniobra hidràulica
AND CentralHidraulica  ; 57K1 Central hidràulica
OUT PujarDesbobinador  ; Pujar Desbobinador
; rung 15: Control baixada desbobinador
LD SP_BaixarDesbo  ; 57SP1 Pulsador baixar desbobinador
AND SP_SeguretatDesbo  ; 57SP3 Pulsador seguretat maniobra hidràulica
AND CentralHidraulica  ; 57K1 Central hidràulica
OUT BaixarDesbobinador  ; 58Y2 Baixar desbobinador
; rung 16: Carrega el valor de diametre del equip del alineador
LD P_0_02s
OR 301.01  ; Senyal diametre desbo busy
CALL DB_DiametreDesbo_PV : _INVDRT201_ReadParameter (MasterUnitNo := &0, NodeNo := &4, ParameterNo := &120, BUSY => 301.01, Value => AuxDiametreDresbo_PV)  ; Senyal diametre desbo busy, Diametre actual desbobinador format %

; rung 17: Escala valor de diametre en mm
LD P_On
MOV(021) DiametreMaximDesbo SclDiaMaxDesbo  ; Diametre màxim desbobinador en mm, Diametre màxim desbo escalat
SCL2(486) AuxDiametreDresbo_PV SclOffsetDiaDesbo AuxCalcul0  ; Diametre actual desbobinador format %, Offset escalat diametre desbo, Auxiliar Calcul
BINS(470) #1 AuxCalcul0 DiametreDesbo_PV  ; Auxiliar Calcul, Diametre desbobinador en mm
; rung 18: Escalat sortida tensió per a la carta de fre
LD P_On
*(420) TensioDesbo_SP DiametreDesbo_PV AuxDCalcul0  ; Consigna de fre al desbobinador, Diametre desbobinador en mm
/L(431) AuxDCalcul0 +200 AuxCalcul0  ; Auxiliar Calcul
SCL(194) AuxCalcul0 D1316 AuxCalcul1  ; Auxiliar Calcul
BIN(023) AuxCalcul1 SortidaFre  ; Auxiliar Calcul
; rung 19: Limitar sortida fre 0..1000 -> 0..10V
LD P_On
OUT TR0
AND<S(312) SortidaFre #0
MOV(021) #0 SortidaFre
LD TR0
AND>S(322) SortidaFre +1000
MOV(021) #1000 SortidaFre

; rung 20: Si màquina parada i desbo a off desbloquejar fre
LDNOT Estat_Preparacio  ; Maquina en estat de preparació
ANDNOT Estat_Marxa  ; Màquina en producció
ANDNOT Estat_Paro  ; Màquina en procés de paro convencional
ANDNOT OffOnDesbo  ; Biestable Off/On desbobinador
MOV(021) +0 SortidaFre
; rung 21: Parell màxim de fre, si màquina en estat d'emergència o màquina parada amb desbo activat
LD Estat_emergència  ; Màquina en estat de paro d'emergència
LDNOT Estat_Preparacio  ; Maquina en estat de preparació
ANDNOT Estat_Marxa  ; Màquina en producció
ANDNOT Estat_Paro  ; Màquina en procés de paro convencional
AND OffOnDesbo  ; Biestable Off/On desbobinador
ORLD
MOV(021) +1000 SortidaFre
; rung 22: Envia consigna de parell al equip amb la sortida analogica connectada al fre
LD P_0_02s
OR 301.00  ; Senyal consigna fre busy
CALL AnalogOutFreDesbo : _INVDRT401_WriteParameter (MasterUnitNo := &0, NodeNo := &4, INVtype := &0, ParameterNo := &7, Value := SortidaFre, BUSY => 301.00)  ; Senyal consigna fre busy
; rung 23: Control enclavament porta seguretat
LD TencatDesbo_Muntat  ; Tencat desbobinador de seguretat muntat a màquina
OUT TR0
ANDNOT FlagVelocitatSeguretat  ; Senyal màquina en velocitat de seguretat
LD TR0
AND FlagVelocitatSeguretat  ; Senyal màquina en velocitat de seguretat
ORNOT TencatDesbo_Muntat  ; Tencat desbobinador de seguretat muntat a màquina
KEEP(011) EnclavamentPortaDesbo  ; 16K1 Enclavament seguretat porta desbobinador

; rung 24: Pilot selector porta seguretat
LD TencatDesbo_Muntat  ; Tencat desbobinador de seguretat muntat a màquina
AND SL_PortaSeguretat  ; 08SL15 Selector obrir porta seguretat
LD EnclavamentPortaDesbo  ; 16K1 Enclavament seguretat porta desbobinador
AND P_1s
ORNOT EnclavamentPortaDesbo  ; 16K1 Enclavament seguretat porta desbobinador
ANDLD
OUT PilotSelectorPorta  ; 08SH15 Pilot selector obrir porta seguretat desbo

### Section Handling

; rung 0: Retard a la desconexió del pistor posició carrega
LD BI_PosicioPerxaCarrega  ; 22BI3 Detector Handling Posicio Carrega
TIM 0303 #50  ; Retard a la desconexió del pisto carrega bobines handling
; rung 1: Retard a la desconexió del pistor vertical
LD BI_PosicioBraçVertical  ; 22BI2 Detector Handling Posicio Vertical
TIM 0302 #50  ; Retard a la desconexió del pisto posició vertical handling
; rung 2: Handling a posicio carregar bobines (Entrar)
LD SP_MovimentHandling  ; 61SP1 Pulsador Moviment Handling
AND BI_PosicioPerxaDesrarrega  ; 22BI4 Detector Handling Posicio Descarrega
AND BI_PosicioBraçVertical  ; 22BI2 Detector Handling Posicio Vertical
AND BI_SeguretatBraçosAmun  ; 14BI3 Posicio braços suport amunt
LD PerxaCarrega  ; 62Y4 Perxa Posicio Carrega
ANDNOT T0303  ; Retard a la desconexió del pisto carrega bobines handling
ANDNOT SP_HandlingStop  ; 61SP2 Pulsador Handling Stop
ORLD
OUT PerxaCarrega  ; 62Y4 Perxa Posicio Carrega
; rung 3: Handling a posicio descarga bobines (Sortir)
LD SP_MovimentHandling  ; 61SP1 Pulsador Moviment Handling
LD BI_PosicioPerxaCarrega  ; 22BI3 Detector Handling Posicio Carrega
LDNOT PerxaDescarrega  ; 62Y3 Perxa Posicio Descarrega
ANDNOT PerxaCarrega  ; 62Y4 Perxa Posicio Carrega
ANDNOT BI_PosicioPerxaCarrega  ; 22BI3 Detector Handling Posicio Carrega
ANDNOT BI_PosicioPerxaDesrarrega  ; 22BI4 Detector Handling Posicio Descarrega
ORLD
ANDLD
AND BI_PosicioBraçVertical  ; 22BI2 Detector Handling Posicio Vertical
LD ExpulsorHome  ; 13B2 Reed Expulsor Home
ORNOT Expulsors_Muntats  ; Expulsors instal.lats a màquina
ANDLD
LD PerxaDescarrega  ; 62Y3 Perxa Posicio Descarrega
ANDNOT BI_PosicioPerxaDesrarrega  ; 22BI4 Detector Handling Posicio Descarrega
ANDNOT SP_HandlingStop  ; 61SP2 Pulsador Handling Stop
ORLD
OUT PerxaDescarrega  ; 62Y3 Perxa Posicio Descarrega

; rung 4: Handling a posicio horitzontal
LD SP_RotacioHandlingHoritzontal  ; 61S1 Pulsador Rotacio Horitzontal Handling
LD BraçHandlingHoritzontal  ; 62Y2 Braç Handling Posicio Hotirzontal
ANDNOT BI_PosicioBraçHoritzontal  ; 22BI1 Detector Handling Posicio Horitzontal
ANDNOT SP_HandlingStop  ; 61SP2 Pulsador Handling Stop
ORLD
AND BI_PosicioPerxaDesrarrega  ; 22BI4 Detector Handling Posicio Descarrega
@LD BI_PosicioPerxaDesrarrega  ; 22BI4 Detector Handling Posicio Descarrega
AND ManAutHandling  ; Handling en manual automàtic
ORLD
OUT BraçHandlingHoritzontal  ; 62Y2 Braç Handling Posicio Hotirzontal
; rung 5: Handling posicio vertical
LD SP_RotacioHandlingVertical  ; 61S1Pulsador Rotacio Vertical Handling
ANDNOT BraçHandlingHoritzontal  ; 62Y2 Braç Handling Posicio Hotirzontal
LD BraçHandlingVertical  ; 62Y1 Braç Handling Posicio Vertical
ANDNOT T0302  ; Retard a la desconexió del pisto posició vertical handling
ANDNOT SP_HandlingStop  ; 61SP2 Pulsador Handling Stop
ORLD
AND BI_PosicioPerxaDesrarrega  ; 22BI4 Detector Handling Posicio Descarrega
OUT BraçHandlingVertical  ; 62Y1 Braç Handling Posicio Vertical
; rung 6: Demanda central hidraulica per al handling
LD PerxaCarrega  ; 62Y4 Perxa Posicio Carrega
OR PerxaDescarrega  ; 62Y3 Perxa Posicio Descarrega
OR BraçHandlingHoritzontal  ; 62Y2 Braç Handling Posicio Hotirzontal
OR BraçHandlingVertical  ; 62Y1 Braç Handling Posicio Vertical
OUT DemHidraHandling  ; Demanda central hidraulica handlind

### Section Expulsors

; rung 0: Seguretat carro endarrera
LD>=S(327) D1405 +1500  ; Error posició pisor 1
AND>=S(327) D1415 +1500  ; Error posicio pisor 2
OUT SeguretatPisorOff  ; Seguretat pisor totalment endavant
; rung 1: Expulsor bobines a mes
LD SP_ActivarExpulsor  ; 13S1Pulsador Activar Expulsor
ANDNOT SeguretatBraçAbaix  ; 14SF2 Final de cursa seguretat posició braços suport rebobinador abaix
AND BI_PosicioPerxaCarrega  ; 22BI3 Detector Handling Posicio Carrega
AND BI_PosicioBraçVertical  ; 22BI2 Detector Handling Posicio Vertical
AND SeguretatPisorOff  ; Seguretat pisor totalment endavant
OUT ActivarExpulsor  ; 13Y1 Expulsor Activat
; rung 2: Expulsor bobines a menys
LD SP_DesactivarExpulsor  ; 13S1Pulsador Desactivar Expulsor
OUT DesactivarExpulsor  ; 13Y2 Desactivar Expulsor

### Section END
; rung 0
END(001)

## Function block _INVDRT201_ReadParameter (Omron library block, body left out)

## Function block _INVDRT401_WriteParameter (Omron library block, body left out)

## Function block Escalat
VAR_INPUT
  In : INT;
  InMax : INT;
  InMin : INT;
  OutMax : INT;
  OutMin : INT;
END_VAR
VAR_OUTPUT
  Out : INT;
END_VAR
VAR
  IncIn : REAL;
  IncOut : REAL;
  m : REAL;
  n : REAL;
END_VAR
(* Calcula els valors de increment de ambdos eixos *)
IncIn:=(int_to_real(InMax)-int_to_real(InMin));
IncOut:=(int_to_real(OutMax)-int_to_real(OutMin));

(* Calcula el pendent de la recta de interpolació *)
m:=IncOut / IncIn;

(* Calcula el offset *)
n:=(int_to_real(OutMax))-(int_to_real(InMax) * m); 

(* Conversió del valor de sortida de real a enter *)
Out:=real_to_int(int_to_real(In)*m + n);

## Function block FriccioEix1
VAR_INPUT
  Tir : INT;
  Decreixent : INT;
  Ample : INT;
  DiametreActual : INT;
  DiametreMaxim : INT;
  DiametreMinim : INT;
  PressioMax : INT;
  MinOut : INT;  (* Valor de sortida minim *)
END_VAR
VAR_OUTPUT
  Pressio : INT;
END_VAR
VAR
  TirDecreixent : REAL;
  DifDiametre : REAL;
  DifActual : REAL;
  SortidaREAL : REAL;
  TirREAL : REAL;
END_VAR
(* Càlcul tir amb decreixent *)
TirREAL:=int_to_real(Tir)/10,0;
DifDiametre:=int_to_real(DiametreMaxim-DiametreMinim);
DifActual:=int_to_real(DiametreActual-DiametreMinim);
If DifActual<0,0 then
	DifActual:=0,0;
end_if;
TirDecreixent:=TirREAL-(TirREAL*DifActual*int_to_real(Decreixent)/(DifDiametre*100,0));

(* Calcul dels bars necesaris per al parell desitjat a l'eix *)
SortidaREAL:=((0,36877*TirDecreixent*int_to_real(DiametreActual))+55,79)/int_to_real(Ample);

(* Escala sortida de Pmax a 100.0% *)
Pressio:=real_to_int(SortidaReal*500,0/int_to_real(PressioMax));

(* Limitació de la sortida 100%..0% *)
if Pressio>500 then 
	Pressio:=500;
elsif Pressio<MinOut then
	Pressio:=MinOut;
end_if;

(*El valor 16384 és el màxim que ens pot donar el nou variador Yaskawa A1000, dona 4000H = 16384DEC; el  model anterior "F7" donava 1400*)
(*Aquest escalat serveix per donar valor a  la sortida FM del nou variador A1000, calculem el valor analógic de 0 a 10VDC per la proporcional del eix 2, l'altre porporcional (eix 1) la agafem del variador V7 del carro*)
(*sortida AM*)

## Function block FriccioEix2
VAR_INPUT
  Tir : INT;
  Decreixent : INT;
  Ample : INT;
  DiametreActual : INT;
  DiametreMaxim : INT;
  DiametreMinim : INT;
  PressioMax : INT;
  MinOut : INT;  (* Valor de sortida minim *)
END_VAR
VAR_OUTPUT
  Pressio : INT;
END_VAR
VAR
  TirDecreixent : REAL;
  DifDiametre : REAL;
  DifActual : REAL;
  SortidaREAL : REAL;
  TirREAL : REAL;
END_VAR
(* Càlcul tir amb decreixent *)
TirREAL:=int_to_real(Tir)/10,0;
DifDiametre:=int_to_real(DiametreMaxim-DiametreMinim);
DifActual:=int_to_real(DiametreActual-DiametreMinim);
If DifActual<0,0 then
	DifActual:=0,0;
end_if;
TirDecreixent:=TirREAL-(TirREAL*DifActual*int_to_real(Decreixent)/(DifDiametre*100,0));

(* Calcul dels bars necesaris per al parell desitjat a l'eix *)
SortidaREAL:=((0,36877*TirDecreixent*int_to_real(DiametreActual))+55,79)/int_to_real(Ample);

(* Escala sortida de Pmax a 100.0% *)
Pressio:=real_to_int(SortidaReal*16384,0/int_to_real(PressioMax));

(* Limitació de la sortida 100%..0% *)
if Pressio>16384 then 
	Pressio:=16384;
elsif Pressio<MinOut then
	Pressio:=MinOut;
end_if;

(*El valor 16384 és el màxim que ens pot donar el nou variador Yaskawa A1000, dona 4000H = 16384DEC; el  model anterior "F7" donava 1400*)
(*Aquest escalat serveix per donar valor a  la sortida FM del nou variador A1000, calculem el valor analógic de 0 a 10VDC per la proporcional del eix 2, l'altre porporcional (eix 1) la agafem del variador V7 del carro*)
(*sortida AM*)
